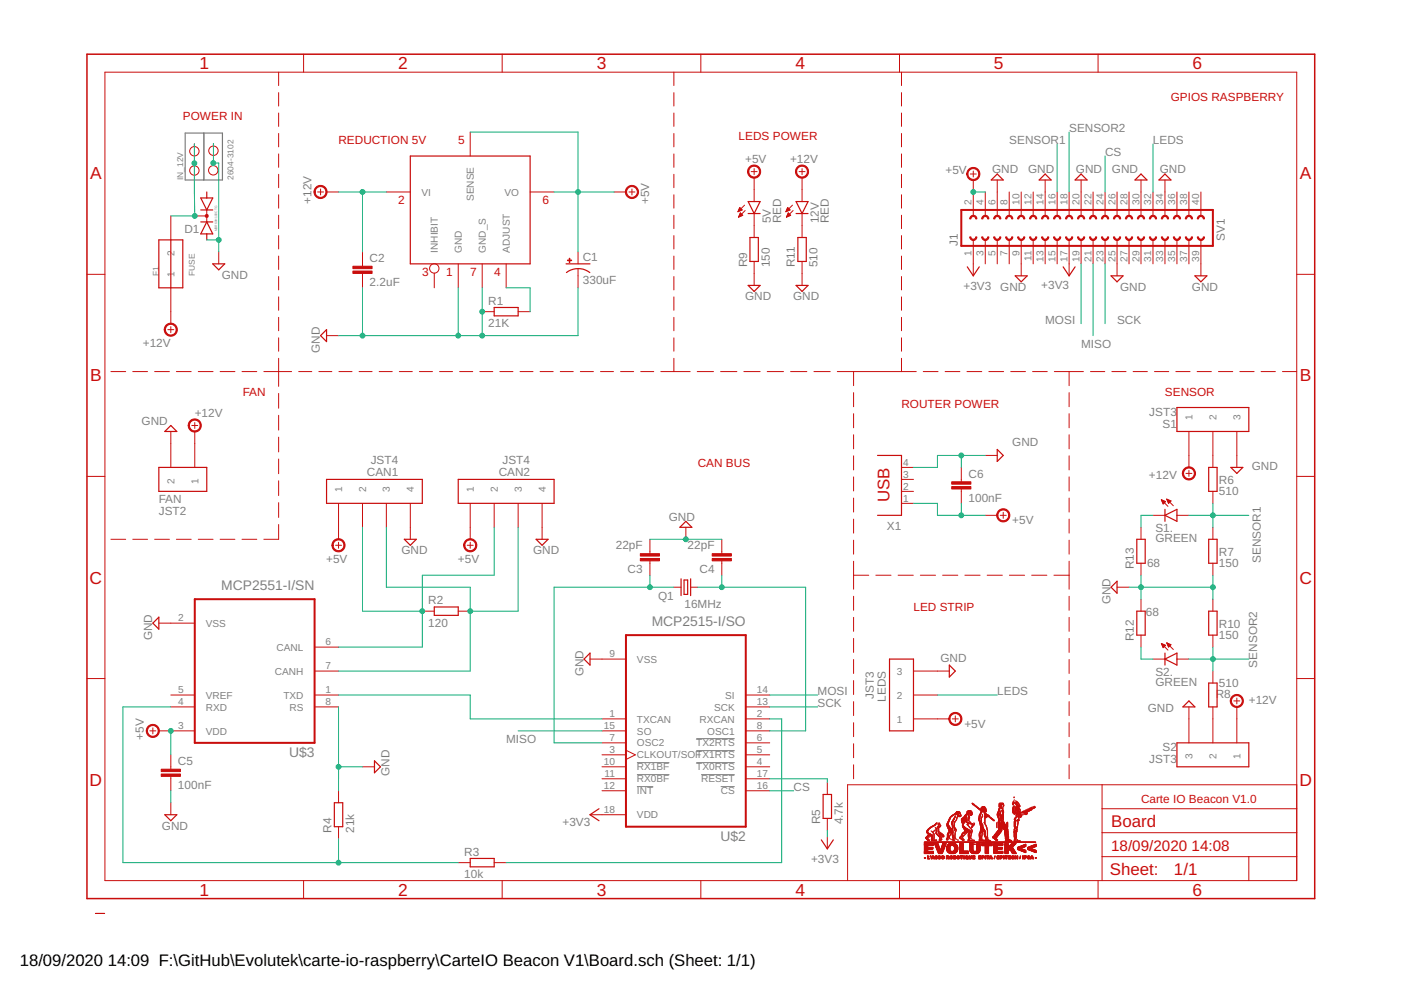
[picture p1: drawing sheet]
<svg xmlns="http://www.w3.org/2000/svg" width="297mm" height="210mm" viewBox="0 0 297 210" stroke-linecap="round" stroke-linejoin="round" font-family="sans-serif">
<defs><g id="words">
<g font-size="3.7" fill="#c90d0c">
<text x="42.3" y="14.7">1</text>
<text x="84.4" y="14.7">2</text>
<text x="126.5" y="14.7">3</text>
<text x="168.6" y="14.7">4</text>
<text x="210.7" y="14.7">5</text>
<text x="252.9" y="14.7">6</text>
<text x="19.1" y="38">A</text>
<text x="275.6" y="38">A</text>
<text x="19.1" y="80.9">B</text>
<text x="275.6" y="80.9">B</text>
<text x="19" y="123.7">C</text>
<text x="275.5" y="123.7">C</text>
<text x="19" y="166.6">D</text>
<text x="275.5" y="166.6">D</text>
<text x="42.3" y="189.9">1</text>
<text x="84.4" y="189.9">2</text>
<text x="126.5" y="189.9">3</text>
<text x="168.6" y="189.9">4</text>
<text x="210.7" y="189.9">5</text>
<text x="252.9" y="189.9">6</text>
</g>
<g font-size="3.6" fill="#c90d0c">
<text x="188.6" y="106.5" transform="rotate(-90 188.6 106.5)">USB</text>
<text x="235.6" y="175.3">Board</text>
<text x="235.3" y="185.6">Sheet:</text>
<text x="248.9" y="185.4">1/1</text>
</g>
<g font-size="3.5">
<text x="4.2" y="204.7">18/09/2020</text>
<text x="22.9" y="204.7">14:09 F:\GitHub\Evolutek\carte-io-raspberry\CarteIO Beacon V1\Board.sch (Sheet: 1/1)</text>
</g>
<g font-size="3.2" fill="#c90d0c">
<text x="235.6" y="180.4">18/09/2020</text>
<text x="252.6" y="180.4">14:08</text>
</g>
<g font-size="2.9" fill="#808080">
<text x="46.9" y="125.1">MCP2551-I/SN</text>
<text x="138.2" y="132.7">MCP2515-I/SO</text>
<text x="61.3" y="160.6">U$3</text>
<text x="152.7" y="178.4">U$2</text>
</g>
<g font-size="2.5" fill="#c90d0c">
<text x="248.2" y="21.4">GPIOS RASPBERRY</text>
<text x="38.8" y="25.5">POWER IN</text>
<text x="156.6" y="29.8">LEDS POWER</text>
<text x="71.8" y="30.5">REDUCTION 5V</text>
<text x="97.2" y="30.5">5</text>
<text x="84.4" y="43.2">2</text>
<text x="115" y="43.2">6</text>
<text x="89.5" y="58.5">3</text>
<text x="94.6" y="58.5">1</text>
<text x="99.7" y="58.5">7</text>
<text x="104.8" y="58.5">4</text>
<text x="51.5" y="83.9">FAN</text>
<text x="247" y="83.9">SENSOR</text>
<text x="191.1" y="86.4">ROUTER POWER</text>
<text x="148" y="99.1">CAN BUS</text>
<text x="193.7" y="129.6">LED STRIP</text>
<text x="241.9" y="170.2">Carte IO Beacon V1.0</text>
</g>
<g font-size="2.5" fill="#808080">
<text x="226.7" y="28">SENSOR2</text>
<text x="158" y="34.5">+5V</text>
<text x="167.5" y="34.5">+12V</text>
<text x="214" y="30.5">SENSOR1</text>
<text x="234.3" y="33.1">CS</text>
<text x="244.5" y="30.5">LEDS</text>
<text x="200.5" y="37">+5V</text>
<text x="210.3" y="36.8">GND</text>
<text x="218" y="36.8">GND</text>
<text x="228.1" y="36.8">GND</text>
<text x="235.7" y="36.8">GND</text>
<text x="245.9" y="36.8">GND</text>
<text x="66.1" y="43.2" transform="rotate(-90 66.1 43.2)">+12V</text>
<text x="137.7" y="43.3" transform="rotate(-90 137.7 43.3)">+5V</text>
<text x="163.4" y="47.3" transform="rotate(-90 163.4 47.3)">5V</text>
<text x="165.6" y="47.3" transform="rotate(-90 165.6 47.3)">RED</text>
<text x="173.6" y="47.3" transform="rotate(-90 173.6 47.3)">12V</text>
<text x="175.8" y="47.3" transform="rotate(-90 175.8 47.3)">RED</text>
<text x="39.1" y="49.3">D1</text>
<text x="203.1" y="52.1" transform="rotate(-90 203.1 52.1)">J1</text>
<text x="259.7" y="51.1" transform="rotate(-90 259.7 51.1)">SV1</text>
<text x="47" y="59.1">GND</text>
<text x="78.4" y="55.6">C2</text>
<text x="123.6" y="55.3">C1</text>
<text x="158.4" y="56.7" transform="rotate(-90 158.4 56.7)">R9</text>
<text x="163.2" y="56.7" transform="rotate(-90 163.2 56.7)">150</text>
<text x="168.5" y="56.7" transform="rotate(-90 168.5 56.7)">R11</text>
<text x="173.3" y="56.7" transform="rotate(-90 173.3 56.7)">510</text>
<text x="78.4" y="60.6">2.2uF</text>
<text x="103.5" y="64.6">R1</text>
<text x="123.6" y="60.1">330uF</text>
<text x="158" y="63.7">GND</text>
<text x="168.1" y="63.7">GND</text>
<text x="204.3" y="61.5">+3V3</text>
<text x="212.1" y="61.6">GND</text>
<text x="220.8" y="61.3">+3V3</text>
<text x="237.5" y="61.6">GND</text>
<text x="252.7" y="61.6">GND</text>
<text x="103.5" y="69.4">21K</text>
<text x="221.6" y="68.6">MOSI</text>
<text x="236.8" y="68.6">SCK</text>
<text x="30.3" y="73.6">+12V</text>
<text x="67.8" y="74.8" transform="rotate(-90 67.8 74.8)">GND</text>
<text x="229.2" y="73.7">MISO</text>
<text x="41.3" y="88.3">+12V</text>
<text x="243.7" y="88.2">JST3</text>
<text x="30" y="90.1">GND</text>
<text x="214.6" y="94.7">GND</text>
<text x="246.5" y="90.7">S1</text>
<text x="77.8" y="100.9">CAN1</text>
<text x="78.6" y="98.3">JST4</text>
<text x="105.7" y="100.9">CAN2</text>
<text x="106.5" y="98.3">JST4</text>
<text x="205.3" y="101.3">C6</text>
<text x="243.6" y="101.5">+12V</text>
<text x="265.4" y="99.7">GND</text>
<text x="33.7" y="106.7">FAN</text>
<text x="205.3" y="106.3">100nF</text>
<text x="258.4" y="104.9">510</text>
<text x="258.4" y="102.7">R6</text>
<text x="33.7" y="109.3">JST2</text>
<text x="141.8" y="110.4">GND</text>
<text x="188.1" y="112.3">X1</text>
<text x="214.6" y="111.2">+5V</text>
<text x="245" y="112.8">S1.</text>
<text x="69.1" y="119.3">+5V</text>
<text x="85.1" y="117.5">GND</text>
<text x="97.1" y="119.3">+5V</text>
<text x="113" y="117.5">GND</text>
<text x="130.6" y="116.5">22pF</text>
<text x="145.8" y="116.5">22pF</text>
<text x="245" y="115">GREEN</text>
<text x="258.4" y="117.9">R7</text>
<text x="267.3" y="119.4" transform="rotate(-90 267.3 119.4)">SENSOR1</text>
<text x="133.1" y="121.6">C3</text>
<text x="148.3" y="121.6">C4</text>
<text x="240.4" y="120.7" transform="rotate(-90 240.4 120.7)">R13</text>
<text x="243.2" y="120.2">68</text>
<text x="258.4" y="120.2">150</text>
<text x="90.8" y="128.1">R2</text>
<text x="139.5" y="127.3">Q1</text>
<text x="145.1" y="128.8">16MHz</text>
<text x="235.4" y="128.1" transform="rotate(-90 235.4 128.1)">GND</text>
<text x="242.9" y="130.6">68</text>
<text x="32.3" y="135.8" transform="rotate(-90 32.3 135.8)">GND</text>
<text x="90.8" y="132.9">120</text>
<text x="240.4" y="135.9" transform="rotate(-90 240.4 135.9)">R12</text>
<text x="258.4" y="135.4">150</text>
<text x="258.4" y="133.2">R10</text>
<text x="123.7" y="143.4" transform="rotate(-90 123.7 143.4)">GND</text>
<text x="199.4" y="140.4">GND</text>
<text x="245" y="143.3">S2.</text>
<text x="266.6" y="141.5" transform="rotate(-90 266.6 141.5)">SENSOR2</text>
<text x="173.3" y="147.4">MOSI</text>
<text x="173.3" y="149.9">SCK</text>
<text x="185.3" y="148.1" transform="rotate(-90 185.3 148.1)">JST3</text>
<text x="187.8" y="148.8" transform="rotate(-90 187.8 148.8)">LEDS</text>
<text x="211.4" y="147.4">LEDS</text>
<text x="245" y="145.4">GREEN</text>
<text x="257.8" y="148.1">R8</text>
<text x="258.4" y="145.6">510</text>
<text x="264.8" y="149.3">+12V</text>
<text x="204.5" y="154.3">+5V</text>
<text x="243.4" y="151">GND</text>
<text x="30.5" y="156.9" transform="rotate(-90 30.5 156.9)">+5V</text>
<text x="107.3" y="157.5">MISO</text>
<text x="243.7" y="161.8">JST3</text>
<text x="246.5" y="159.3">S2</text>
<text x="37.7" y="167.3">100nF</text>
<text x="37.7" y="162.2">C5</text>
<text x="82.6" y="164.5" transform="rotate(-90 82.6 164.5)">GND</text>
<text x="168.3" y="167.7">CS</text>
<text x="34.3" y="175.9">GND</text>
<text x="70.3" y="176.6" transform="rotate(-90 70.3 176.6)">R4</text>
<text x="75.1" y="176.6" transform="rotate(-90 75.1 176.6)">21k</text>
<text x="119.3" y="175.1">+3V3</text>
<text x="173.9" y="174.8" transform="rotate(-90 173.9 174.8)">R5</text>
<text x="178.7" y="174.8" transform="rotate(-90 178.7 174.8)">4.7k</text>
<text x="98.4" y="181.4">R3</text>
<text x="171.9" y="182.9">+3V3</text>
<text x="98.4" y="186.2">10k</text>
</g>
<g font-size="2.1" fill="#808080">
<text x="89.3" y="41.5">VI</text>
<text x="107" y="41.5">VO</text>
<text x="100.5" y="42.6" transform="rotate(-90 100.5 42.6)">SENSE</text>
<text x="206" y="43.4" transform="rotate(-90 206 43.4)">2</text>
<text x="208.5" y="43.4" transform="rotate(-90 208.5 43.4)">4</text>
<text x="211.1" y="43.4" transform="rotate(-90 211.1 43.4)">6</text>
<text x="213.6" y="43.4" transform="rotate(-90 213.6 43.4)">8</text>
<text x="216.2" y="43.4" transform="rotate(-90 216.2 43.4)">10</text>
<text x="218.7" y="43.4" transform="rotate(-90 218.7 43.4)">12</text>
<text x="221.2" y="43.4" transform="rotate(-90 221.2 43.4)">14</text>
<text x="223.8" y="43.4" transform="rotate(-90 223.8 43.4)">16</text>
<text x="226.3" y="43.4" transform="rotate(-90 226.3 43.4)">18</text>
<text x="228.9" y="43.4" transform="rotate(-90 228.9 43.4)">20</text>
<text x="231.4" y="43.4" transform="rotate(-90 231.4 43.4)">22</text>
<text x="233.9" y="43.4" transform="rotate(-90 233.9 43.4)">24</text>
<text x="236.5" y="43.4" transform="rotate(-90 236.5 43.4)">26</text>
<text x="239" y="43.4" transform="rotate(-90 239 43.4)">28</text>
<text x="241.6" y="43.4" transform="rotate(-90 241.6 43.4)">30</text>
<text x="244.1" y="43.4" transform="rotate(-90 244.1 43.4)">32</text>
<text x="246.6" y="43.4" transform="rotate(-90 246.6 43.4)">34</text>
<text x="249.2" y="43.4" transform="rotate(-90 249.2 43.4)">36</text>
<text x="251.7" y="43.4" transform="rotate(-90 251.7 43.4)">38</text>
<text x="254.3" y="43.4" transform="rotate(-90 254.3 43.4)">40</text>
<text x="92.8" y="53.6" transform="rotate(-90 92.8 53.6)">INHIBIT</text>
<text x="97.9" y="53.6" transform="rotate(-90 97.9 53.6)">GND</text>
<text x="103" y="53.6" transform="rotate(-90 103 53.6)">GND_S</text>
<text x="108.1" y="53.6" transform="rotate(-90 108.1 53.6)">ADJUST</text>
<text x="37" y="58.7" transform="rotate(-90 37 58.7)">1</text>
<text x="37" y="54.4" transform="rotate(-90 37 54.4)">2</text>
<text x="206" y="54.4" transform="rotate(-90 206 54.4)">1</text>
<text x="208.5" y="54.4" transform="rotate(-90 208.5 54.4)">3</text>
<text x="211.1" y="54.4" transform="rotate(-90 211.1 54.4)">5</text>
<text x="213.6" y="54.4" transform="rotate(-90 213.6 54.4)">7</text>
<text x="216.2" y="54.4" transform="rotate(-90 216.2 54.4)">9</text>
<text x="218.7" y="55.4" transform="rotate(-90 218.7 55.4)">11</text>
<text x="221.2" y="55.6" transform="rotate(-90 221.2 55.6)">13</text>
<text x="223.8" y="55.6" transform="rotate(-90 223.8 55.6)">15</text>
<text x="226.3" y="55.6" transform="rotate(-90 226.3 55.6)">17</text>
<text x="228.9" y="55.6" transform="rotate(-90 228.9 55.6)">19</text>
<text x="231.4" y="55.6" transform="rotate(-90 231.4 55.6)">21</text>
<text x="233.9" y="55.6" transform="rotate(-90 233.9 55.6)">23</text>
<text x="236.5" y="55.6" transform="rotate(-90 236.5 55.6)">25</text>
<text x="239" y="55.6" transform="rotate(-90 239 55.6)">27</text>
<text x="241.6" y="55.6" transform="rotate(-90 241.6 55.6)">29</text>
<text x="244.1" y="55.6" transform="rotate(-90 244.1 55.6)">31</text>
<text x="246.6" y="55.6" transform="rotate(-90 246.6 55.6)">33</text>
<text x="249.2" y="55.6" transform="rotate(-90 249.2 55.6)">35</text>
<text x="251.7" y="55.6" transform="rotate(-90 251.7 55.6)">37</text>
<text x="254.3" y="55.6" transform="rotate(-90 254.3 55.6)">39</text>
<text x="252.8" y="89.1" transform="rotate(-90 252.8 89.1)">1</text>
<text x="257.9" y="89.1" transform="rotate(-90 257.9 89.1)">2</text>
<text x="263" y="89.1" transform="rotate(-90 263 89.1)">3</text>
<text x="191.5" y="101.3">3</text>
<text x="191.5" y="98.7">4</text>
<text x="37" y="102.6" transform="rotate(-90 37 102.6)">2</text>
<text x="42.1" y="102.6" transform="rotate(-90 42.1 102.6)">1</text>
<text x="72.5" y="104.4" transform="rotate(-90 72.5 104.4)">1</text>
<text x="77.6" y="104.4" transform="rotate(-90 77.6 104.4)">2</text>
<text x="82.7" y="104.4" transform="rotate(-90 82.7 104.4)">3</text>
<text x="87.8" y="104.4" transform="rotate(-90 87.8 104.4)">4</text>
<text x="100.5" y="104.4" transform="rotate(-90 100.5 104.4)">1</text>
<text x="105.5" y="104.4" transform="rotate(-90 105.5 104.4)">2</text>
<text x="110.6" y="104.4" transform="rotate(-90 110.6 104.4)">3</text>
<text x="115.7" y="104.4" transform="rotate(-90 115.7 104.4)">4</text>
<text x="191.5" y="106.4">1</text>
<text x="191.5" y="103.8">2</text>
<text x="37.8" y="131.8">2</text>
<text x="43.6" y="132.9">VSS</text>
<text x="58.7" y="138">CANL</text>
<text x="69" y="136.8">6</text>
<text x="58.3" y="143">CANH</text>
<text x="69" y="141.9">7</text>
<text x="129.2" y="139.4">9</text>
<text x="135.1" y="140.5">VSS</text>
<text x="190.1" y="143">3</text>
<text x="37.8" y="149.5">4</text>
<text x="37.8" y="147">5</text>
<text x="43.6" y="148.1">VREF</text>
<text x="60.1" y="148.1">TXD</text>
<text x="69" y="149.5">8</text>
<text x="69" y="147">1</text>
<text x="153.8" y="148.1">SI</text>
<text x="160.4" y="149.5">13</text>
<text x="160.4" y="147">14</text>
<text x="190.1" y="148.1">2</text>
<text x="37.8" y="154.6">3</text>
<text x="43.6" y="155.7">VDD</text>
<text x="43.6" y="150.7">RXD</text>
<text x="61.4" y="150.7">RS</text>
<text x="128" y="154.6">15</text>
<text x="129.2" y="152.1">1</text>
<text x="135.1" y="155.7">SO</text>
<text x="135.1" y="153.2">TXCAN</text>
<text x="148.3" y="153.2">RXCAN</text>
<text x="150" y="155.7">OSC1</text>
<text x="151.4" y="150.7">SCK</text>
<text x="160.4" y="154.6">8</text>
<text x="160.4" y="152.1">2</text>
<text x="190.1" y="153.2">1</text>
<text x="129.2" y="159.7">3</text>
<text x="129.2" y="157.2">7</text>
<text x="135.1" y="160.8">CLKOUT/SOF</text>
<text x="135.1" y="158.3">OSC2</text>
<text x="147.6" y="160.8">TX1RTS</text>
<text x="147.6" y="158.3">TX2RTS</text>
<text x="160.4" y="159.7">5</text>
<text x="160.4" y="157.2">6</text>
<text x="252.8" y="161" transform="rotate(-90 252.8 161)">3</text>
<text x="257.9" y="161" transform="rotate(-90 257.9 161)">2</text>
<text x="263" y="161" transform="rotate(-90 263 161)">1</text>
<text x="128" y="167.3">12</text>
<text x="128" y="162.2">10</text>
<text x="128.2" y="164.8">11</text>
<text x="135.1" y="165.9">RX0BF</text>
<text x="135.1" y="163.4">RX1BF</text>
<text x="147.6" y="163.4">TX0RTS</text>
<text x="148.7" y="165.9">RESET</text>
<text x="160.4" y="167.3">16</text>
<text x="160.4" y="164.8">17</text>
<text x="160.4" y="162.2">4</text>
<text x="128" y="172.4">18</text>
<text x="135.1" y="173.5">VDD</text>
<text x="135.1" y="168.4">INT</text>
<text x="152.8" y="168.4">CS</text>
</g>
<g font-size="1.8" fill="#808080">
<text x="38.8" y="38.2" transform="rotate(-90 38.8 38.2)">IN_12V</text>
<text x="49.5" y="38.2" transform="rotate(-90 49.5 38.2)">2604-3102</text>
<text x="33.7" y="58.5" transform="rotate(-90 33.7 58.5)">F1</text>
<text x="41.3" y="58.5" transform="rotate(-90 41.3 58.5)">FUSE</text>
</g>
<text font-size=".7" fill="#808080" x="46" y="49.1" transform="rotate(-90 46 49.1)">MBR60H100CTG</text>
</g></defs>
<path d="M39.3 28.2h7.9v10h-7.9zM43.2 28.2v10" fill="none" stroke="#808080" stroke-width=".25"/>
<path d="M147.6 159.2h8.2M147.6 156.6h8.2M135 166.8h3.5M135 164.2h6.9M135 161.7h6.9M147.6 161.7h8.2M148.7 164.2h7.1M152.8 166.8h3" fill="none" stroke="#808080" stroke-width=".21"/>
<g fill="#c90d0c" stroke="#c90d0c" stroke-width=".21">
<path d="M196.6 182.1h.5z"/>
<path d="M197.4 182.1h.3z"/>
<path d="M198 182.1h.2z"/>
<path d="M198.3 182.1h.4z"/>
<path d="M199 182.1h.3z"/>
<path d="M199.7 182.1h.3z"/>
<path d="M200.6 182.1h.3z"/>
<path d="M201.1 182.1h.2z"/>
<path d="M201.5 182.1h.4z"/>
<path d="M202.1 182.1h.5z"/>
<path d="M203 182.1h.3z"/>
<path d="M203.8 182.1h.2z"/>
<path d="M204.3 182.1h.2z"/>
<path d="M204.8 182.1h.5z"/>
<path d="M205.5 182.1h.4z"/>
<path d="M206.2 182.1h.5z"/>
<path d="M207.5 182.1h.5z"/>
<path d="M208.2 182.1h.1z"/>
<path d="M208.8 182.1h.2z"/>
<path d="M209.3 182.1h.2z"/>
<path d="M209.7 182.1h.3z"/>
<path d="M210.2 182.1h.3z"/>
<path d="M211.4 182.1h.5z"/>
<path d="M212.1 182.1h.1z"/>
<path d="M212.7 182.1h.2z"/>
<path d="M213.2 182.1h.2z"/>
<path d="M213.8 182.1h.5z"/>
<path d="M214.6 182.1h.3z"/>
<path d="M215.1 182.1h.2z"/>
<path d="M215.6 182.1h.2z"/>
<path d="M216.8 182.1h.2z"/>
<path d="M217.1 182.1h.3z"/>
<path d="M217.9 182.1h.4z"/>
<path d="M218.4 182.1h.2z"/>
<path d="M218.9 182.1h.2z"/>
<path d="M196.6 182l.5 .1z"/>
<path d="M197.4 182l.3 .1z"/>
<path d="M197.9 182l.3 .1z"/>
<path d="M198.3 182l.4 .1z"/>
<path d="M198.9 182l.5 .1z"/>
<path d="M199.6 182l.6 .1z"/>
<path d="M200.6 182l.3 .1z"/>
<path d="M201 182l.3 .1z"/>
<path d="M201.4 182l.5 .1z"/>
<path d="M202.1 182l.6 .1z"/>
<path d="M202.9 182l.5 .1z"/>
<path d="M203.8 182l.2 .1z"/>
<path d="M204.3 182l.2 .1z"/>
<path d="M204.7 182l.6 .1z"/>
<path d="M205.5 182l.5 .1z"/>
<path d="M206.2 182l.5 .1z"/>
<path d="M207.5 182l.5 .1z"/>
<path d="M208.1 182l.3 .1z"/>
<path d="M208.8 182l.2 .1z"/>
<path d="M209.3 182l.2 .1z"/>
<path d="M209.7 182l.3 .1z"/>
<path d="M210.2 182l.2 .1z"/>
<path d="M211.4 182l.5 .1z"/>
<path d="M212 182l.3 .1z"/>
<path d="M212.7 182l.2 .1z"/>
<path d="M213.2 182l.2 .1z"/>
<path d="M213.8 182l.5 .1z"/>
<path d="M214.5 182l.5 .1z"/>
<path d="M215.1 182l.3 .1z"/>
<path d="M215.6 182l.2 .1z"/>
<path d="M216.8 182l.2 .1z"/>
<path d="M217.1 182l.3 .1z"/>
<path d="M217.9 182l.4 .1z"/>
<path d="M218.5 182l.2 .1z"/>
<path d="M218.9 182l.2 .1z"/>
<path d="M196.6 182h.5z"/>
<path d="M197.5 182h.6z"/>
<path d="M198.2 182h.3z"/>
<path d="M198.5 182h.3z"/>
<path d="M198.9 182h.2z"/>
<path d="M199.2 182h.2z"/>
<path d="M199.6 182h.6z"/>
<path d="M200.6 182h.3z"/>
<path d="M201 182h.3z"/>
<path d="M201.4 182h.6z"/>
<path d="M202.1 182h.6z"/>
<path d="M202.9 182h.6z"/>
<path d="M203.8 182h.2z"/>
<path d="M204.3 182h.2z"/>
<path d="M204.7 182h.6z"/>
<path d="M205.4 182h.6z"/>
<path d="M206.2 182h.5z"/>
<path d="M207.5 182h.5z"/>
<path d="M208.1 182h.3z"/>
<path d="M208.8 182h.2z"/>
<path d="M209.3 182h.2z"/>
<path d="M209.7 182h.7z"/>
<path d="M211.4 182h.5z"/>
<path d="M212 182h.3z"/>
<path d="M212.7 182h.2z"/>
<path d="M213.2 182h.2z"/>
<path d="M213.8 182h.5z"/>
<path d="M214.5 182h.5z"/>
<path d="M215.1 182h.3z"/>
<path d="M215.6 182h.2z"/>
<path d="M216.8 182h.2z"/>
<path d="M217.1 182h.3z"/>
<path d="M217.8 182h.3z"/>
<path d="M218.1 182h.3z"/>
<path d="M218.5 182h.6z"/>
<path d="M196 181.9l.2 .1z"/>
<path d="M196.6 181.9l.2 .1z"/>
<path d="M197.5 181.9l.6 .1z"/>
<path d="M198.2 181.9l.2 .1z"/>
<path d="M198.6 181.9l.2 .1z"/>
<path d="M198.9 181.9l.2 .1z"/>
<path d="M199.2 181.9l.3 .1z"/>
<path d="M199.6 181.9l.2 .1z"/>
<path d="M200 181.9l.2 .1z"/>
<path d="M200.6 181.9l.3 .1z"/>
<path d="M201 181.9l.2 .1z"/>
<path d="M201.4 181.9l.2 .1z"/>
<path d="M201.8 181.9l.2 .1z"/>
<path d="M202.1 181.9l.2 .1z"/>
<path d="M202.5 181.9l.2 .1z"/>
<path d="M202.8 181.9l.3 .1z"/>
<path d="M203.2 181.9l.3 .1z"/>
<path d="M203.8 181.9l.2 .1z"/>
<path d="M204.3 181.9l.2 .1z"/>
<path d="M204.6 181.9l.3 .1z"/>
<path d="M204.9 181.9l.4 .1z"/>
<path d="M205.4 181.9l.2 .1z"/>
<path d="M205.8 181.9l.2 .1z"/>
<path d="M206.2 181.9l.2 .1z"/>
<path d="M207.5 181.9l.2 .1z"/>
<path d="M208.1 181.9l.3 .1z"/>
<path d="M208.8 181.9l.2 .1z"/>
<path d="M209.3 181.9l.2 .1z"/>
<path d="M209.8 181.9l.6 .1z"/>
<path d="M211.4 181.9l.2 .1z"/>
<path d="M212 181.9l.3 .1z"/>
<path d="M212.7 181.9l.2 .1z"/>
<path d="M213.2 181.9l.2 .1z"/>
<path d="M213.7 181.9l.3 .1z"/>
<path d="M214.4 181.9l.3 .1z"/>
<path d="M214.8 181.9l.2 .1z"/>
<path d="M215.1 181.9l.3 .1z"/>
<path d="M215.6 181.9l.2 .1z"/>
<path d="M216.8 181.9l.2 .1z"/>
<path d="M217.1 181.9l.3 .1z"/>
<path d="M217.8 181.9l.2 .1z"/>
<path d="M218.2 181.9l.2 .1z"/>
<path d="M218.5 181.9l.6 .1z"/>
<path d="M219.5 181.9l.3 .1z"/>
<path d="M196 181.9h.2z"/>
<path d="M196.6 181.9h.2z"/>
<path d="M197.5 181.9h.6z"/>
<path d="M198.6 181.9h.2z"/>
<path d="M199.2 181.9h.3z"/>
<path d="M199.5 181.9h.3z"/>
<path d="M200 181.9h.2z"/>
<path d="M200.6 181.9h.3z"/>
<path d="M201 181.9h.2z"/>
<path d="M201.3 181.9h.3z"/>
<path d="M201.8 181.9h.2z"/>
<path d="M202.1 181.9h.2z"/>
<path d="M202.5 181.9h.2z"/>
<path d="M202.8 181.9h.2z"/>
<path d="M203.3 181.9h.2z"/>
<path d="M203.8 181.9h.2z"/>
<path d="M204.3 181.9h.2z"/>
<path d="M204.6 181.9h.2z"/>
<path d="M205.1 181.9h.2z"/>
<path d="M205.4 181.9h.2z"/>
<path d="M205.8 181.9h.2z"/>
<path d="M206.2 181.9h.2z"/>
<path d="M207.5 181.9h.2z"/>
<path d="M208.1 181.9h.3z"/>
<path d="M208.8 181.9h.2z"/>
<path d="M209.3 181.9h.2z"/>
<path d="M209.8 181.9h.6z"/>
<path d="M211.4 181.9h.2z"/>
<path d="M212 181.9h.3z"/>
<path d="M212.7 181.9h.2z"/>
<path d="M213.2 181.9h.2z"/>
<path d="M213.7 181.9h.3z"/>
<path d="M214.4 181.9h.2z"/>
<path d="M214.9 181.9h.1z"/>
<path d="M215.1 181.9h.3z"/>
<path d="M215.6 181.9h.2z"/>
<path d="M216.8 181.9h.2z"/>
<path d="M217.1 181.9h.3z"/>
<path d="M218.2 181.9h.2z"/>
<path d="M218.5 181.9h.6z"/>
<path d="M219.5 181.9h.3z"/>
<path d="M196 181.8l.2 .1z"/>
<path d="M196.6 181.8l.2 .1z"/>
<path d="M197.5 181.8l.3 .1z"/>
<path d="M197.8 181.8l.3 .1z"/>
<path d="M198.4 181.8l.4 .1z"/>
<path d="M199.1 181.8l.3 .1z"/>
<path d="M199.5 181.8l.2 .1z"/>
<path d="M200 181.8l.3 .1z"/>
<path d="M200.7 181.8l.5 .1z"/>
<path d="M201.3 181.8l.3 .1z"/>
<path d="M201.8 181.8l.2 .1z"/>
<path d="M202.1 181.8l.6 .1z"/>
<path d="M202.8 181.8l.2 .1z"/>
<path d="M203.3 181.8l.2 .1z"/>
<path d="M203.8 181.8l.2 .1z"/>
<path d="M204.3 181.8l.2 .1z"/>
<path d="M204.6 181.8l.2 .1z"/>
<path d="M205.1 181.8l.2 .1z"/>
<path d="M205.4 181.8l.2 .1z"/>
<path d="M205.8 181.8l.2 .1z"/>
<path d="M206.2 181.8l.5 .1z"/>
<path d="M207.5 181.8l.5 .1z"/>
<path d="M208.1 181.8l.5 .1z"/>
<path d="M208.8 181.8l.2 .1z"/>
<path d="M209.3 181.8l.2 .1z"/>
<path d="M209.8 181.8l.2 .1z"/>
<path d="M210.1 181.8l.3 .1z"/>
<path d="M211.4 181.8l.5 .1z"/>
<path d="M212 181.8l.5 .1z"/>
<path d="M212.7 181.8l.2 .1z"/>
<path d="M213.2 181.8l.2 .1z"/>
<path d="M213.8 181.8l.5 .1z"/>
<path d="M214.4 181.8l.2 .1z"/>
<path d="M215.1 181.8l.7 .1z"/>
<path d="M216.8 181.8l.2 .1z"/>
<path d="M217.1 181.8l.6 .1z"/>
<path d="M218 181.8l.4 .1z"/>
<path d="M218.5 181.8l.2 .1z"/>
<path d="M218.8 181.8l.2 .1z"/>
<path d="M219.5 181.8l.3 .1z"/>
<path d="M196.6 181.8h.2z"/>
<path d="M197.5 181.8h.3z"/>
<path d="M197.8 181.8h.3z"/>
<path d="M198.3 181.8h.5z"/>
<path d="M199 181.8h.4z"/>
<path d="M199.5 181.8h.2z"/>
<path d="M200 181.8h.3z"/>
<path d="M200.7 181.8h.5z"/>
<path d="M201.3 181.8h.3z"/>
<path d="M201.8 181.8h.2z"/>
<path d="M202.1 181.8h.6z"/>
<path d="M202.8 181.8h.2z"/>
<path d="M203.3 181.8h.2z"/>
<path d="M203.8 181.8h.2z"/>
<path d="M204.3 181.8h.2z"/>
<path d="M204.6 181.8h.2z"/>
<path d="M205.1 181.8h.2z"/>
<path d="M205.4 181.8h.2z"/>
<path d="M205.8 181.8h.2z"/>
<path d="M206.2 181.8h.5z"/>
<path d="M207.5 181.8h.5z"/>
<path d="M208.1 181.8h.6z"/>
<path d="M208.8 181.8h.2z"/>
<path d="M209.3 181.8h.2z"/>
<path d="M209.8 181.8h.3z"/>
<path d="M210.1 181.8h.2z"/>
<path d="M211.4 181.8h.5z"/>
<path d="M212 181.8h.6z"/>
<path d="M212.7 181.8h.2z"/>
<path d="M213.2 181.8h.2z"/>
<path d="M213.8 181.8h.5z"/>
<path d="M214.4 181.8h.2z"/>
<path d="M215.1 181.8h.7z"/>
<path d="M216.8 181.8h.2z"/>
<path d="M217.2 181.8h.5z"/>
<path d="M217.9 181.8h.5z"/>
<path d="M218.6 181.8h.1z"/>
<path d="M218.8 181.8h.2z"/>
<path d="M196.6 181.7l.2 .1z"/>
<path d="M197.6 181.7l.2 .1z"/>
<path d="M197.8 181.7l.2 .1z"/>
<path d="M198.2 181.7l.5 .1z"/>
<path d="M198.9 181.7l.4 .1z"/>
<path d="M199.5 181.7l.2 .1z"/>
<path d="M200 181.7l.3 .1z"/>
<path d="M200.7 181.7l.6 .1z"/>
<path d="M201.3 181.7l.3 .1z"/>
<path d="M201.8 181.7l.2 .1z"/>
<path d="M202.1 181.7l.6 .1z"/>
<path d="M202.8 181.7l.2 .1z"/>
<path d="M203.3 181.7l.2 .1z"/>
<path d="M203.8 181.7l.2 .1z"/>
<path d="M204.3 181.7l.2 .1z"/>
<path d="M204.6 181.7l.2 .1z"/>
<path d="M205.1 181.7l.2 .1z"/>
<path d="M205.4 181.7l.2 .1z"/>
<path d="M205.8 181.7l.2 .1z"/>
<path d="M206.2 181.7l.5 .1z"/>
<path d="M207.5 181.7l.5 .1z"/>
<path d="M208.1 181.7l.3 .1z"/>
<path d="M208.5 181.7l.2 .1z"/>
<path d="M208.8 181.7l.2 .1z"/>
<path d="M209.3 181.7l.2 .1z"/>
<path d="M209.8 181.7l.3 .1z"/>
<path d="M210.1 181.7l.2 .1z"/>
<path d="M211.4 181.7l.5 .1z"/>
<path d="M212 181.7l.3 .1z"/>
<path d="M212.4 181.7l.2 .1z"/>
<path d="M212.7 181.7l.2 .1z"/>
<path d="M213.2 181.7l.2 .1z"/>
<path d="M213.8 181.7l.5 .1z"/>
<path d="M214.4 181.7l.2 .1z"/>
<path d="M215.1 181.7l.7 .1z"/>
<path d="M216.8 181.7l.2 .1z"/>
<path d="M217.1 181.7l.3 .1z"/>
<path d="M217.5 181.7l.2 .1z"/>
<path d="M217.8 181.7l.5 .1z"/>
<path d="M218.6 181.7l.2 .1z"/>
<path d="M218.8 181.7l.2 .1z"/>
<path d="M196.6 181.7h.2z"/>
<path d="M197.2 181.7h.2z"/>
<path d="M197.6 181.7h.4z"/>
<path d="M198.2 181.7h.3z"/>
<path d="M198.9 181.7h.3z"/>
<path d="M199.5 181.7h.3z"/>
<path d="M200 181.7h.2z"/>
<path d="M200.6 181.7h.3z"/>
<path d="M201.1 181.7h.2z"/>
<path d="M201.4 181.7h.2z"/>
<path d="M201.8 181.7h.2z"/>
<path d="M202.1 181.7h.2z"/>
<path d="M202.5 181.7h.2z"/>
<path d="M202.8 181.7h.2z"/>
<path d="M203.3 181.7h.2z"/>
<path d="M203.8 181.7h.2z"/>
<path d="M204.3 181.7h.2z"/>
<path d="M204.6 181.7h.2z"/>
<path d="M205.1 181.7h.2z"/>
<path d="M205.4 181.7h.2z"/>
<path d="M205.8 181.7h.2z"/>
<path d="M206.2 181.7h.2z"/>
<path d="M207.5 181.7h.2z"/>
<path d="M208.1 181.7h.3z"/>
<path d="M208.5 181.7h.2z"/>
<path d="M208.8 181.7h.2z"/>
<path d="M209.3 181.7h.2z"/>
<path d="M209.9 181.7h.3z"/>
<path d="M211.4 181.7h.2z"/>
<path d="M212 181.7h.3z"/>
<path d="M212.4 181.7h.2z"/>
<path d="M212.7 181.7h.2z"/>
<path d="M213.2 181.7h.2z"/>
<path d="M213.7 181.7h.3z"/>
<path d="M214.4 181.7h.2z"/>
<path d="M215.1 181.7h.3z"/>
<path d="M215.6 181.7h.2z"/>
<path d="M216.8 181.7h.2z"/>
<path d="M217.1 181.7h.3z"/>
<path d="M217.5 181.7h.2z"/>
<path d="M217.8 181.7h.3z"/>
<path d="M218.6 181.7h.4z"/>
<path d="M196.6 181.6l.2 .1z"/>
<path d="M197.2 181.6l.2 .1z"/>
<path d="M197.6 181.6l.4 .1z"/>
<path d="M198.2 181.6l.2 .1z"/>
<path d="M198.6 181.6l.2 .1z"/>
<path d="M198.9 181.6l.2 .1z"/>
<path d="M199.2 181.6l.2 .1z"/>
<path d="M199.6 181.6l.2 .1z"/>
<path d="M199.9 181.6l.3 .1z"/>
<path d="M200.6 181.6l.3 .1z"/>
<path d="M201 181.6l.3 .1z"/>
<path d="M201.4 181.6l.2 .1z"/>
<path d="M201.7 181.6l.3 .1z"/>
<path d="M202.1 181.6l.2 .1z"/>
<path d="M202.5 181.6l.2 .1z"/>
<path d="M202.8 181.6l.3 .1z"/>
<path d="M203.2 181.6l.3 .1z"/>
<path d="M203.6 181.6l.6 .1z"/>
<path d="M204.3 181.6l.2 .1z"/>
<path d="M204.7 181.6l.2 .1z"/>
<path d="M205 181.6l.3 .1z"/>
<path d="M205.4 181.6l.2 .1z"/>
<path d="M205.8 181.6l.2 .1z"/>
<path d="M206.2 181.6l.2 .1z"/>
<path d="M207.5 181.6l.2 .1z"/>
<path d="M208.1 181.6l.3 .1z"/>
<path d="M208.5 181.6l.2 .1z"/>
<path d="M208.8 181.6l.2 .1z"/>
<path d="M209.1 181.6l.6 .1z"/>
<path d="M209.9 181.6l.3 .1z"/>
<path d="M211.4 181.6l.2 .1z"/>
<path d="M212 181.6l.3 .1z"/>
<path d="M212.4 181.6l.2 .1z"/>
<path d="M212.7 181.6l.2 .1z"/>
<path d="M213 181.6l.6 .1z"/>
<path d="M213.7 181.6l.3 .1z"/>
<path d="M214.4 181.6l.3 .1z"/>
<path d="M214.8 181.6l.2 .1z"/>
<path d="M215.1 181.6l.3 .1z"/>
<path d="M215.6 181.6l.2 .1z"/>
<path d="M216.8 181.6l.2 .1z"/>
<path d="M217.1 181.6l.3 .1z"/>
<path d="M217.5 181.6l.2 .1z"/>
<path d="M217.8 181.6l.2 .1z"/>
<path d="M218.2 181.6l.2 .1z"/>
<path d="M218.6 181.6l.4 .1z"/>
<path d="M196.6 181.6h.2z"/>
<path d="M197.2 181.6h.2z"/>
<path d="M197.7 181.6h.3z"/>
<path d="M198.2 181.6h.6z"/>
<path d="M198.9 181.6h.5z"/>
<path d="M199.6 181.6h.6z"/>
<path d="M200.7 181.6h.6z"/>
<path d="M201.4 181.6h.6z"/>
<path d="M202.1 181.6h.6z"/>
<path d="M202.9 181.6h.5z"/>
<path d="M203.5 181.6h.7z"/>
<path d="M204.3 181.6h.2z"/>
<path d="M204.7 181.6h.5z"/>
<path d="M205.4 181.6h.2z"/>
<path d="M205.8 181.6h.2z"/>
<path d="M206.2 181.6h.5z"/>
<path d="M207.5 181.6h.5z"/>
<path d="M208.1 181.6h.6z"/>
<path d="M208.8 181.6h.2z"/>
<path d="M209.1 181.6h.6z"/>
<path d="M209.9 181.6h.3z"/>
<path d="M211.4 181.6h.5z"/>
<path d="M212 181.6h.6z"/>
<path d="M212.7 181.6h.2z"/>
<path d="M213 181.6h.6z"/>
<path d="M213.8 181.6h.5z"/>
<path d="M214.5 181.6h.5z"/>
<path d="M215.1 181.6h.3z"/>
<path d="M215.6 181.6h.2z"/>
<path d="M216.8 181.6h.2z"/>
<path d="M217.2 181.6h.5z"/>
<path d="M217.8 181.6h.6z"/>
<path d="M218.6 181.6h.3z"/>
<path d="M196.6 181.5h.2z"/>
<path d="M197.2 181.5h.2z"/>
<path d="M197.7 181.5h.3z"/>
<path d="M198.3 181.5h.4z"/>
<path d="M198.9 181.5h.5z"/>
<path d="M199.6 181.5h.6z"/>
<path d="M200.7 181.5h.5z"/>
<path d="M201.5 181.5h.4z"/>
<path d="M202.1 181.5h.6z"/>
<path d="M202.9 181.5h.5z"/>
<path d="M203.5 181.5h.7z"/>
<path d="M204.3 181.5h.2z"/>
<path d="M204.7 181.5h.5z"/>
<path d="M205.4 181.5h.2z"/>
<path d="M205.8 181.5h.2z"/>
<path d="M206.2 181.5h.5z"/>
<path d="M207.5 181.5h.5z"/>
<path d="M208.1 181.5h.6z"/>
<path d="M208.8 181.5h.2z"/>
<path d="M209.1 181.5h.6z"/>
<path d="M210 181.5h.2z"/>
<path d="M206.3 179h.5z"/>
<path d="M212 181.5h.6z"/>
<path d="M212.7 181.5h.2z"/>
<path d="M213 181.5h.6z"/>
<path d="M213.8 181.5h.5z"/>
<path d="M214.5 181.5h.5z"/>
<path d="M215.1 181.5h.3z"/>
<path d="M215.6 181.5h.2z"/>
<path d="M216.8 181.5h.2z"/>
<path d="M217.1 181.5h.6z"/>
<path d="M217.9 181.5h.4z"/>
<path d="M218.7 181.5h.2z"/>
<path d="M197.7 181.5h.2z"/>
<path d="M198.4 181.5h.2z"/>
<path d="M199 181.5h.3z"/>
<path d="M199.7 181.5h.3z"/>
<path d="M200.6 181.5h.5z"/>
<path d="M201.6 181.5h.2z"/>
<path d="M202.2 181.5h.4z"/>
<path d="M203 181.5h.3z"/>
<path d="M203.6 181.5h.6z"/>
<path d="M204.8 181.5h.3z"/>
<path d="M205.9 181.5h.1z"/>
<path d="M208.2 181.5h.3z"/>
<path d="M211.4 181.5h.5z"/>
<path d="M212.1 181.5h.3z"/>
<path d="M214.6 181.5h.3z"/>
<path d="M215.2 181.5h.1z"/>
<path d="M217.1 181.5h.5z"/>
<path d="M218 181.5h.2z"/>
<path d="M196 181h1.9z"/>
<path d="M199 181h.7z"/>
<path d="M201.5 181h.8z"/>
<path d="M203.5 181h1.8z"/>
<path d="M206.2 181h1z"/>
<path d="M208.9 181h.7z"/>
<path d="M20.2 193.7h2z"/>
<path d="M213.1 181h.7z"/>
<path d="M214.7 181h.8z"/>
<path d="M196 180.9l1.9 .1z"/>
<path d="M199 180.9l.8 .1z"/>
<path d="M201.3 180.9l1.2 .1z"/>
<path d="M203.5 180.9l1.8 .1z"/>
<path d="M206.1 180.9l1.2 .1z"/>
<path d="M208.9 180.9l.7 .1z"/>
<path d="M210.7 180.9l1.9 .1z"/>
<path d="M213 180.9l.8 .1z"/>
<path d="M214.6 180.9l.9 .1z"/>
<path d="M196 180.8l1.9 .1z"/>
<path d="M198.9 180.8l.9 .1z"/>
<path d="M201.2 180.8l1.4 .1z"/>
<path d="M203.5 180.8l1.8 .1z"/>
<path d="M206 180.8l1.4 .1z"/>
<path d="M208.9 180.8l.7 .1z"/>
<path d="M210.7 180.8l1.9 .1z"/>
<path d="M213 180.8l.8 .1z"/>
<path d="M214.6 180.8l.8 .1z"/>
<path d="M196 180.8h1.9z"/>
<path d="M198.9 180.8h1z"/>
<path d="M201.1 180.8h1.6z"/>
<path d="M203.5 180.8h1.8z"/>
<path d="M205.9 180.8h1.6z"/>
<path d="M208.9 180.8h.7z"/>
<path d="M210.7 180.8h1.9z"/>
<path d="M213 180.8h.8z"/>
<path d="M214.6 180.8h.8z"/>
<path d="M196 180.7l1.9 .1z"/>
<path d="M198.9 180.7l1 .1z"/>
<path d="M201 180.7l1.7 .1z"/>
<path d="M203.5 180.7l1.8 .1z"/>
<path d="M205.9 180.7l1.7 .1z"/>
<path d="M208.9 180.7l.7 .1z"/>
<path d="M210.7 180.7l1.9 .1z"/>
<path d="M213 180.7l.8 .1z"/>
<path d="M214.5 180.7l.9 .1z"/>
<path d="M196 180.7h1.9z"/>
<path d="M198.9 180.7h1z"/>
<path d="M201 180.7h1.8z"/>
<path d="M203.5 180.7h1.8z"/>
<path d="M205.8 180.7h1.8z"/>
<path d="M208.9 180.7h.7z"/>
<path d="M210.7 180.7h1.9z"/>
<path d="M213 180.7h.8z"/>
<path d="M214.5 180.7h.9z"/>
<path d="M217.3 180.7h.2z"/>
<path d="M219.4 180.7h.3z"/>
<path d="M214.5 180.7h.8z"/>
<path d="M217.2 180.7h.3z"/>
<path d="M219.3 180.7h.4z"/>
<path d="M196 180.6h1.9z"/>
<path d="M198.8 180.6h1.1z"/>
<path d="M200.9 180.6h2z"/>
<path d="M203.5 180.6h1.8z"/>
<path d="M205.7 180.6h2z"/>
<path d="M208.9 180.6h.7z"/>
<path d="M210.7 180.6h1.9z"/>
<path d="M213 180.6h.8z"/>
<path d="M214.5 180.6h.8z"/>
<path d="M217 180.6h.5z"/>
<path d="M219.2 180.6h.5z"/>
<path d="M214.4 180.6h.9z"/>
<path d="M216.9 180.6h.6z"/>
<path d="M219 180.6h.7z"/>
<path d="M196 180.5h1.9z"/>
<path d="M198.8 180.5h1.1z"/>
<path d="M200.9 180.5h.9z"/>
<path d="M201.9 180.5h1z"/>
<path d="M203.5 180.5h1.8z"/>
<path d="M205.7 180.5h2.1z"/>
<path d="M208.9 180.5h.7z"/>
<path d="M210.7 180.5h1.9z"/>
<path d="M213 180.5h.8z"/>
<path d="M214.4 180.5h.8z"/>
<path d="M216.7 180.5h.8z"/>
<path d="M218.9 180.5h.8z"/>
<path d="M196 180.4l.7 .1z"/>
<path d="M198.8 180.4l1.2 .1z"/>
<path d="M200.8 180.4l.8 .1z"/>
<path d="M202.1 180.4l.9 .1z"/>
<path d="M203.5 180.4l1.8 .1z"/>
<path d="M205.7 180.4l.8 .1z"/>
<path d="M206.9 180.4l.9 .1z"/>
<path d="M208.9 180.4l.7 .1z"/>
<path d="M210.7 180.4l.7 .1z"/>
<path d="M213 180.4l.8 .1z"/>
<path d="M214.4 180.4l.8 .1z"/>
<path d="M216.7 180.4l.8 .1z"/>
<path d="M218.8 180.4l.9 .1z"/>
<path d="M196 180.4h.7z"/>
<path d="M198.8 180.4h1.2z"/>
<path d="M200.8 180.4h.8z"/>
<path d="M202.2 180.4h.8z"/>
<path d="M203.5 180.4h.7z"/>
<path d="M205.6 180.4h.8z"/>
<path d="M207 180.4h.8z"/>
<path d="M208.9 180.4h.7z"/>
<path d="M210.7 180.4h.7z"/>
<path d="M213 180.4h.8z"/>
<path d="M214.3 180.4h.9z"/>
<path d="M216.5 180.4h1z"/>
<path d="M218.7 180.4h1z"/>
<path d="M196 180.3l.7 .1z"/>
<path d="M198.7 180.3l1.3 .1z"/>
<path d="M200.7 180.3l.8 .1z"/>
<path d="M202.3 180.3l.7 .1z"/>
<path d="M203.5 180.3l.7 .1z"/>
<path d="M205.6 180.3l.8 .1z"/>
<path d="M207.1 180.3l.7 .1z"/>
<path d="M208.9 180.3l.7 .1z"/>
<path d="M210.7 180.3l.7 .1z"/>
<path d="M213 180.3l.8 .1z"/>
<path d="M214.3 180.3l.8 .1z"/>
<path d="M216.4 180.3l1.1 .1z"/>
<path d="M218.5 180.3l1.2 .1z"/>
<path d="M196 180.3h.7z"/>
<path d="M198.7 180.3h1.3z"/>
<path d="M200.7 180.3h.8z"/>
<path d="M202.3 180.3h.7z"/>
<path d="M203.5 180.3h.7z"/>
<path d="M205.6 180.3h.7z"/>
<path d="M207.1 180.3h.7z"/>
<path d="M208.9 180.3h.7z"/>
<path d="M210.7 180.3h.7z"/>
<path d="M213 180.3h.9z"/>
<path d="M214.3 180.3h.8z"/>
<path d="M216.2 180.3h1.3z"/>
<path d="M218.4 180.3h1.3z"/>
<path d="M196 180.2l.7 .1z"/>
<path d="M198.7 180.2l.6 .1z"/>
<path d="M199.4 180.2l.6 .1z"/>
<path d="M200.7 180.2l.8 .1z"/>
<path d="M202.3 180.2l.7 .1z"/>
<path d="M203.5 180.2l.7 .1z"/>
<path d="M205.6 180.2l.7 .1z"/>
<path d="M207.1 180.2l.7 .1z"/>
<path d="M208.9 180.2l.7 .1z"/>
<path d="M210.7 180.2l.7 .1z"/>
<path d="M213 180.2l1 .1z"/>
<path d="M214.3 180.2l.8 .1z"/>
<path d="M216.1 180.2l1.3 .1z"/>
<path d="M218.3 180.2l1.3 .1z"/>
<path d="M196 180.2h.7z"/>
<path d="M198.7 180.2h.6z"/>
<path d="M199.4 180.2h.7z"/>
<path d="M200.7 180.2h.7z"/>
<path d="M202.3 180.2h.7z"/>
<path d="M203.5 180.2h.7z"/>
<path d="M205.6 180.2h.7z"/>
<path d="M207.1 180.2h.7z"/>
<path d="M208.9 180.2h.7z"/>
<path d="M210.7 180.2h.7z"/>
<path d="M213 180.2h1z"/>
<path d="M214.2 180.2h.8z"/>
<path d="M216 180.2h1.3z"/>
<path d="M218.1 180.2h1.4z"/>
<path d="M196 180.1l.7 .1z"/>
<path d="M198.7 180.1l.6 .1z"/>
<path d="M199.4 180.1l.7 .1z"/>
<path d="M200.7 180.1l.7 .1z"/>
<path d="M202.3 180.1l.8 .1z"/>
<path d="M203.5 180.1l.7 .1z"/>
<path d="M205.6 180.1l.7 .1z"/>
<path d="M207.1 180.1l.7 .1z"/>
<path d="M208.9 180.1l.7 .1z"/>
<path d="M210.7 180.1l.7 .1z"/>
<path d="M213 180.1l1.1 .1z"/>
<path d="M214.2 180.1l.8 .1z"/>
<path d="M215.8 180.1l1.3 .1z"/>
<path d="M218 180.1l1.3 .1z"/>
<path d="M196 180.1h.7z"/>
<path d="M198.6 180.1h.7z"/>
<path d="M199.5 180.1h.6z"/>
<path d="M200.7 180.1h.7z"/>
<path d="M202.4 180.1h.7z"/>
<path d="M203.5 180.1h.7z"/>
<path d="M205.6 180.1h.7z"/>
<path d="M207.1 180.1h.7z"/>
<path d="M208.9 180.1h.7z"/>
<path d="M210.7 180.1h.7z"/>
<path d="M213 180.1h1.1z"/>
<path d="M214.2 180.1h.8z"/>
<path d="M215.7 180.1h1.3z"/>
<path d="M217.9 180.1h1.3z"/>
<path d="M196 180l.7 .1z"/>
<path d="M198.6 180l.7 .1z"/>
<path d="M199.5 180l.7 .1z"/>
<path d="M200.7 180l.7 .1z"/>
<path d="M202.4 180l.7 .1z"/>
<path d="M203.5 180l.7 .1z"/>
<path d="M205.6 180l.7 .1z"/>
<path d="M207.1 180l.7 .1z"/>
<path d="M208.9 180l.7 .1z"/>
<path d="M210.7 180l.7 .1z"/>
<path d="M213 180l1.9 .1z"/>
<path d="M215.7 180l1.2 .1z"/>
<path d="M217.9 180l1.2 .1z"/>
<path d="M196 180h1.8z"/>
<path d="M198.6 180h.7z"/>
<path d="M199.5 180h.7z"/>
<path d="M200.7 180h.7z"/>
<path d="M202.4 180h.7z"/>
<path d="M203.5 180h.7z"/>
<path d="M205.6 180h.7z"/>
<path d="M207.1 180h.7z"/>
<path d="M208.9 180h.7z"/>
<path d="M210.7 180h1.8z"/>
<path d="M213 180h1.9z"/>
<path d="M215.7 180h1z"/>
<path d="M217.9 180h1z"/>
<path d="M196 179.9l1.8 .1z"/>
<path d="M198.6 179.9l.6 .1z"/>
<path d="M199.5 179.9l.6 .1z"/>
<path d="M200.7 179.9l.7 .1z"/>
<path d="M202.4 179.9l.7 .1z"/>
<path d="M203.5 179.9l.7 .1z"/>
<path d="M205.6 179.9l.7 .1z"/>
<path d="M207.1 179.9l.7 .1z"/>
<path d="M208.9 179.9l.7 .1z"/>
<path d="M210.7 179.9l1.8 .1z"/>
<path d="M213 179.9l1.9 .1z"/>
<path d="M215.8 179.9l.8 .1z"/>
<path d="M217.9 179.9l.9 .1z"/>
<path d="M196 179.9h1.8z"/>
<path d="M198.6 179.9h.6z"/>
<path d="M199.5 179.9h.7z"/>
<path d="M200.7 179.9h.7z"/>
<path d="M202.4 179.9h.7z"/>
<path d="M203.5 179.9h.7z"/>
<path d="M205.6 179.9h.7z"/>
<path d="M207.1 179.9h.7z"/>
<path d="M208.9 179.9h.7z"/>
<path d="M210.7 179.9h1.8z"/>
<path d="M213 179.9h1.8z"/>
<path d="M215.7 179.9h.8z"/>
<path d="M217.9 179.9h.7z"/>
<path d="M196 179.8l1.8 .1z"/>
<path d="M198.5 179.8l.7 .1z"/>
<path d="M199.5 179.8l.7 .1z"/>
<path d="M200.7 179.8l.7 .1z"/>
<path d="M202.4 179.8l.7 .1z"/>
<path d="M203.5 179.8l.7 .1z"/>
<path d="M205.6 179.8l.7 .1z"/>
<path d="M207.1 179.8l.7 .1z"/>
<path d="M208.9 179.8l.7 .1z"/>
<path d="M210.7 179.8l1.8 .1z"/>
<path d="M213 179.8l1.8 .1z"/>
<path d="M215.7 179.8l.8 .1z"/>
<path d="M217.9 179.8l.7 .1z"/>
<path d="M196 179.8h1.8z"/>
<path d="M198.5 179.8h.7z"/>
<path d="M199.6 179.8h.7z"/>
<path d="M200.7 179.8h.7z"/>
<path d="M202.4 179.8h.7z"/>
<path d="M203.5 179.8h.7z"/>
<path d="M205.6 179.8h.7z"/>
<path d="M207.1 179.8h.7z"/>
<path d="M208.9 179.8h.7z"/>
<path d="M210.7 179.8h1.8z"/>
<path d="M213 179.8h1.8z"/>
<path d="M215.7 179.8h1z"/>
<path d="M217.9 179.8h.9z"/>
<path d="M196 179.7l1.8 .1z"/>
<path d="M198.5 179.7l.7 .1z"/>
<path d="M199.6 179.7l.7 .1z"/>
<path d="M200.7 179.7l.7 .1z"/>
<path d="M202.4 179.7l.7 .1z"/>
<path d="M203.5 179.7l.7 .1z"/>
<path d="M205.6 179.7l.7 .1z"/>
<path d="M207.1 179.7l.7 .1z"/>
<path d="M208.9 179.7l.7 .1z"/>
<path d="M210.7 179.7l1.8 .1z"/>
<path d="M213 179.7l1.7 .1z"/>
<path d="M215.7 179.7l1 .1z"/>
<path d="M217.9 179.7l1 .1z"/>
<path d="M196 179.7h1.8z"/>
<path d="M198.5 179.7h.7z"/>
<path d="M199.6 179.7h.7z"/>
<path d="M200.7 179.7h.7z"/>
<path d="M202.4 179.7h.7z"/>
<path d="M203.5 179.7h.7z"/>
<path d="M205.6 179.7h.7z"/>
<path d="M207.1 179.7h.7z"/>
<path d="M208.9 179.7h.7z"/>
<path d="M210.7 179.7h1.8z"/>
<path d="M213 179.7h1.7z"/>
<path d="M215.7 179.7h1.2z"/>
<path d="M217.9 179.7h1.2z"/>
<path d="M196 179.6l1.8 .1z"/>
<path d="M198.5 179.6l.6 .1z"/>
<path d="M199.6 179.6l.7 .1z"/>
<path d="M200.7 179.6l.7 .1z"/>
<path d="M202.4 179.6l.7 .1z"/>
<path d="M203.5 179.6l.7 .1z"/>
<path d="M205.6 179.6l.7 .1z"/>
<path d="M207.1 179.6l.7 .1z"/>
<path d="M208.9 179.6l.7 .1z"/>
<path d="M210.7 179.6l1.8 .1z"/>
<path d="M213 179.6l1.7 .1z"/>
<path d="M215.7 179.6l1.3 .1z"/>
<path d="M217.9 179.6l1.3 .1z"/>
<path d="M196 179.6h.7z"/>
<path d="M198.4 179.6h.7z"/>
<path d="M199.6 179.6h.7z"/>
<path d="M200.7 179.6h.7z"/>
<path d="M202.3 179.6h.8z"/>
<path d="M203.5 179.6h.7z"/>
<path d="M205.6 179.6h.7z"/>
<path d="M207.1 179.6h.7z"/>
<path d="M208.9 179.6h.7z"/>
<path d="M210.7 179.6h.7z"/>
<path d="M213 179.6h1.7z"/>
<path d="M215.8 179.6h1.4z"/>
<path d="M218 179.6h1.3z"/>
<path d="M196 179.5l.7 .1z"/>
<path d="M198.4 179.5l.7 .1z"/>
<path d="M199.6 179.5l.7 .1z"/>
<path d="M200.7 179.5l.7 .1z"/>
<path d="M202.3 179.5l.7 .1z"/>
<path d="M203.5 179.5l.7 .1z"/>
<path d="M205.6 179.5l.7 .1z"/>
<path d="M207.1 179.5l.7 .1z"/>
<path d="M208.9 179.5l.7 .1z"/>
<path d="M210.7 179.5l.7 .1z"/>
<path d="M213 179.5l.8 .1z"/>
<path d="M213.9 179.5l.8 .1z"/>
<path d="M216 179.5l1.3 .1z"/>
<path d="M218.2 179.5l1.3 .1z"/>
<path d="M196 179.5h.7z"/>
<path d="M198.4 179.5h.7z"/>
<path d="M199.7 179.5h.7z"/>
<path d="M200.7 179.5h.8z"/>
<path d="M202.3 179.5h.7z"/>
<path d="M203.5 179.5h.7z"/>
<path d="M205.6 179.5h.7z"/>
<path d="M207.1 179.5h.7z"/>
<path d="M208.9 179.5h.7z"/>
<path d="M210.7 179.5h.7z"/>
<path d="M213 179.5h.8z"/>
<path d="M213.9 179.5h.9z"/>
<path d="M216.2 179.5h1.3z"/>
<path d="M218.3 179.5h1.3z"/>
<path d="M196 179.4l.7 .1z"/>
<path d="M198.4 179.4l.7 .1z"/>
<path d="M199.7 179.4l.7 .1z"/>
<path d="M200.7 179.4l.8 .1z"/>
<path d="M202.3 179.4l.7 .1z"/>
<path d="M203.5 179.4l.7 .1z"/>
<path d="M205.6 179.4l.7 .1z"/>
<path d="M207.1 179.4l.7 .1z"/>
<path d="M208.9 179.4l.7 .1z"/>
<path d="M210.7 179.4l.7 .1z"/>
<path d="M213 179.4l.8 .1z"/>
<path d="M213.9 179.4l.9 .1z"/>
<path d="M216.2 179.4l1.3 .1z"/>
<path d="M218.4 179.4l1.3 .1z"/>
<path d="M196 179.4h.7z"/>
<path d="M198.4 179.4h.7z"/>
<path d="M199.7 179.4h.7z"/>
<path d="M200.7 179.4h.8z"/>
<path d="M202.2 179.4h.8z"/>
<path d="M203.5 179.4h.7z"/>
<path d="M205.6 179.4h.7z"/>
<path d="M207.1 179.4h.7z"/>
<path d="M208.9 179.4h.7z"/>
<path d="M210.7 179.4h.7z"/>
<path d="M213 179.4h.8z"/>
<path d="M214 179.4h.9z"/>
<path d="M216.4 179.4h1.1z"/>
<path d="M218.5 179.4h1.2z"/>
<path d="M196 179.3l.7 .1z"/>
<path d="M198.3 179.3l.7 .1z"/>
<path d="M199.7 179.3l.7 .1z"/>
<path d="M200.8 179.3l.8 .1z"/>
<path d="M202.2 179.3l.8 .1z"/>
<path d="M203.5 179.3l.7 .1z"/>
<path d="M205.6 179.3l.7 .1z"/>
<path d="M207.1 179.3l.7 .1z"/>
<path d="M208.9 179.3l.7 .1z"/>
<path d="M210.7 179.3l.7 .1z"/>
<path d="M213 179.3l.8 .1z"/>
<path d="M214 179.3l.9 .1z"/>
<path d="M216.5 179.3l1 .1z"/>
<path d="M218.7 179.3l1 .1z"/>
<path d="M196 179.3h.7z"/>
<path d="M198.3 179.3h.7z"/>
<path d="M199.7 179.3h.7z"/>
<path d="M200.8 179.3h.9z"/>
<path d="M202.1 179.3h.9z"/>
<path d="M203.5 179.3h.7z"/>
<path d="M205.6 179.3h.7z"/>
<path d="M207.1 179.3h.7z"/>
<path d="M208.2 179.3h2.2z"/>
<path d="M210.7 179.3h.7z"/>
<path d="M213 179.3h.8z"/>
<path d="M214.1 179.3h.9z"/>
<path d="M216.7 179.3h.8z"/>
<path d="M218.8 179.3h.9z"/>
<path d="M196 179.2l1.8 .1z"/>
<path d="M198.3 179.2l.7 .1z"/>
<path d="M199.7 179.2l.7 .1z"/>
<path d="M200.9 179.2l2 .1z"/>
<path d="M203.5 179.2l.7 .1z"/>
<path d="M205.6 179.2l.7 .1z"/>
<path d="M207.1 179.2l.7 .1z"/>
<path d="M208.2 179.2l2.2 .1z"/>
<path d="M210.7 179.2l1.9 .1z"/>
<path d="M213 179.2l.8 .1z"/>
<path d="M214.1 179.2l.9 .1z"/>
<path d="M216.8 179.2l.7 .1z"/>
<path d="M218.9 179.2l.8 .1z"/>
<path d="M196 179.2h1.9z"/>
<path d="M198.3 179.2h.7z"/>
<path d="M199.8 179.2h.6z"/>
<path d="M200.9 179.2h2z"/>
<path d="M203.5 179.2h.7z"/>
<path d="M205.6 179.2h.7z"/>
<path d="M207.1 179.2h.7z"/>
<path d="M208.2 179.2h2.2z"/>
<path d="M210.7 179.2h1.9z"/>
<path d="M213 179.2h.8z"/>
<path d="M214.1 179.2h1z"/>
<path d="M216.9 179.2h.6z"/>
<path d="M219.1 179.2h.6z"/>
<path d="M196 179.1l1.9 .1z"/>
<path d="M198.3 179.1l.7 .1z"/>
<path d="M199.8 179.1l.7 .1z"/>
<path d="M200.9 179.1l2 .1z"/>
<path d="M203.5 179.1l.7 .1z"/>
<path d="M205.6 179.1l.7 .1z"/>
<path d="M207.1 179.1l.7 .1z"/>
<path d="M208.2 179.1l2.2 .1z"/>
<path d="M210.7 179.1l1.9 .1z"/>
<path d="M213 179.1l.8 .1z"/>
<path d="M214.2 179.1l.9 .1z"/>
<path d="M217 179.1l.5 .1z"/>
<path d="M219.2 179.1l.5 .1z"/>
<path d="M196 179.1h1.9z"/>
<path d="M198.2 179.1h.8z"/>
<path d="M199.8 179.1h.7z"/>
<path d="M201 179.1h1.8z"/>
<path d="M203.5 179.1h.7z"/>
<path d="M205.6 179.1h.7z"/>
<path d="M207.1 179.1h.7z"/>
<path d="M208.2 179.1h2.2z"/>
<path d="M210.7 179.1h1.9z"/>
<path d="M213 179.1h.8z"/>
<path d="M214.2 179.1h1z"/>
<path d="M217.2 179.1h.3z"/>
<path d="M219.4 179.1h.3z"/>
<path d="M196 179l1.9 .1z"/>
<path d="M198.2 179l.7 .1z"/>
<path d="M199.8 179l.8 .1z"/>
<path d="M201 179l1.8 .1z"/>
<path d="M203.5 179l.7 .1z"/>
<path d="M205.6 179l.7 .1z"/>
<path d="M207.1 179l.7 .1z"/>
<path d="M208.2 179l2.2 .1z"/>
<path d="M210.7 179l1.9 .1z"/>
<path d="M213 179l.8 .1z"/>
<path d="M214.3 179l.9 .1z"/>
<path d="M217.3 179l.2 .1z"/>
<path d="M219.4 179l.3 .1z"/>
<path d="M196 179h1.9z"/>
<path d="M198.2 179h.7z"/>
<path d="M199.8 179h.8z"/>
<path d="M201 179h1.7z"/>
<path d="M203.5 179h.7z"/>
<path d="M205.6 179h.7z"/>
<path d="M207.1 179h.7z"/>
<path d="M208.2 179h2.2z"/>
<path d="M210.7 179h1.9z"/>
<path d="M213 179h.8z"/>
<path d="M214.4 179h.9z"/>
<path d="M196 178.9l1.9 .1z"/>
<path d="M198.2 178.9l.7 .1z"/>
<path d="M199.8 178.9l.8 .1z"/>
<path d="M201.1 178.9l1.5 .1z"/>
<path d="M203.5 178.9l.7 .1z"/>
<path d="M205.6 178.9l.7 .1z"/>
<path d="M207.1 178.9l.7 .1z"/>
<path d="M208.2 178.9l2.2 .1z"/>
<path d="M210.7 178.9l1.9 .1z"/>
<path d="M213 178.9l.8 .1z"/>
<path d="M214.4 178.9l.9 .1z"/>
<path d="M196 178.9h1.9z"/>
<path d="M198.2 178.9h.7z"/>
<path d="M199.9 178.9h.7z"/>
<path d="M201.2 178.9h1.4z"/>
<path d="M203.5 178.9h.7z"/>
<path d="M205.6 178.9h.7z"/>
<path d="M207.1 178.9h.7z"/>
<path d="M208.2 178.9h2.2z"/>
<path d="M210.7 178.9h1.9z"/>
<path d="M213 178.9h.8z"/>
<path d="M214.4 178.9h1z"/>
<path d="M196 178.8l1.9 .1z"/>
<path d="M198.1 178.8l.8 .1z"/>
<path d="M199.9 178.8l.7 .1z"/>
<path d="M201.3 178.8l1.1 .1z"/>
<path d="M203.5 178.8l.7 .1z"/>
<path d="M205.6 178.8l.7 .1z"/>
<path d="M207.1 178.8l.7 .1z"/>
<path d="M208.2 178.8l2.2 .1z"/>
<path d="M210.7 178.8l1.9 .1z"/>
<path d="M213 178.8l.8 .1z"/>
<path d="M214.5 178.8l.9 .1z"/>
<path d="M196 178.8h1.8z"/>
<path d="M198.1 178.8h.7z"/>
<path d="M199.9 178.8h.7z"/>
<path d="M201.5 178.8h.8z"/>
<path d="M203.5 178.8h.7z"/>
<path d="M205.6 178.8h.7z"/>
<path d="M207.1 178.8h.7z"/>
<path d="M208.2 178.8h2.2z"/>
<path d="M210.7 178.8h1.9z"/>
<path d="M213.1 178.8h.7z"/>
<path d="M214.5 178.8h.9z"/>
<path d="M195.9 178.6h23.7z"/>
<path d="M196 178.5l23.6 .1z"/>
<path d="M214 178.4h.5z"/>
<path d="M215.1 178.4h1.2z"/>
<path d="M209 178.3l.3 .1z"/>
<path d="M209.7 178.3l.3 .1z"/>
<path d="M213.1 178.3l.5 .1z"/>
<path d="M213.8 178.3l.7 .1z"/>
<path d="M215 178.3l1.3 .1z"/>
<path d="M208.5 178.3h.2z"/>
<path d="M208.9 178.3h.9z"/>
<path d="M213.1 178.3h1.4z"/>
<path d="M215 178.3h.2z"/>
<path d="M205.3 178.2h1.3z"/>
<path d="M207.6 178.2h.4z"/>
<path d="M208.1 178.2h.4z"/>
<path d="M208.9 178.2h.7z"/>
<path d="M213.1 178.2h1.4z"/>
<path d="M197.5 178.2h1.1z"/>
<path d="M202 178.2h.4z"/>
<path d="M205.2 178.2h.8z"/>
<path d="M207.6 178.2h.8z"/>
<path d="M208.9 178.2h.2z"/>
<path d="M213.1 178.2h1.3z"/>
<path d="M196.6 178.1l.5 .1z"/>
<path d="M197.5 178.1l1.1 .1z"/>
<path d="M199.1 178.1l.4 .1z"/>
<path d="M202 178.1l.4 .1z"/>
<path d="M204 178.1l.3 .1z"/>
<path d="M205.2 178.1l.5 .1z"/>
<path d="M207.6 178.1l.3 .1z"/>
<path d="M208 178.1l.2 .1z"/>
<path d="M208.9 178.1l.2 .1z"/>
<path d="M211.1 178.1l.4 .1z"/>
<path d="M213.2 178.1l1 .1z"/>
<path d="M196.6 178.1h.4z"/>
<path d="M197.5 178.1h.2z"/>
<path d="M199.1 178.1h.3z"/>
<path d="M200.7 178.1h.3z"/>
<path d="M202 178.1h.2z"/>
<path d="M204 178.1h.2z"/>
<path d="M205.2 178.1h.4z"/>
<path d="M207.6 178.1h.2z"/>
<path d="M208.9 178.1h.2z"/>
<path d="M211 178.1h.5z"/>
<path d="M213.2 178.1h.9z"/>
<path d="M215 178.1h.2z"/>
<path d="M196.5 178l.2 .1z"/>
<path d="M197.5 178l.2 .1z"/>
<path d="M199.2 178l.2 .1z"/>
<path d="M200.6 178l.5 .1z"/>
<path d="M203.9 178l.2 .1z"/>
<path d="M205.3 178l.2 .1z"/>
<path d="M207.6 178l.2 .1z"/>
<path d="M208.9 178l.2 .1z"/>
<path d="M211 178l.5 .1z"/>
<path d="M213.2 178l.8 .1z"/>
<path d="M215.1 178l.1 .1z"/>
<path d="M196.5 177.9l.2 .1z"/>
<path d="M197.5 177.9l.2 .1z"/>
<path d="M199.2 177.9l.2 .1z"/>
<path d="M200.7 177.9l.3 .1z"/>
<path d="M202 177.9l.2 .1z"/>
<path d="M205.3 177.9l.2 .1z"/>
<path d="M207.6 177.9l.3 .1z"/>
<path d="M208.9 177.9l.3 .1z"/>
<path d="M211 177.9l.5 .1z"/>
<path d="M213.3 177.9l.5 .1z"/>
<path d="M215.1 177.9l.1 .1z"/>
<path d="M196.4 177.9h.2z"/>
<path d="M197.5 177.9h.2z"/>
<path d="M200.7 177.9h.2z"/>
<path d="M203.8 177.9h.2z"/>
<path d="M205.3 177.9h.2z"/>
<path d="M207.7 177.9h.2z"/>
<path d="M209 177.9h.2z"/>
<path d="M210.9 177.9h.4z"/>
<path d="M213.2 177.9h.5z"/>
<path d="M215.1 177.9h.2z"/>
<path d="M202.1 177.9h.2z"/>
<path d="M203.7 177.9h.2z"/>
<path d="M205.4 177.9h.2z"/>
<path d="M210.8 177.9h.5z"/>
<path d="M196.4 177.8h.2z"/>
<path d="M197.5 177.8h.2z"/>
<path d="M200.7 177.8h.2z"/>
<path d="M202.1 177.8h.2z"/>
<path d="M203.7 177.8h.2z"/>
<path d="M205.4 177.8h.2z"/>
<path d="M207.7 177.8h.2z"/>
<path d="M209 177.8h.2z"/>
<path d="M210.8 177.8h.5z"/>
<path d="M213.2 177.8h.5z"/>
<path d="M196.3 177.8h.2z"/>
<path d="M200.7 177.8h.3z"/>
<path d="M203.6 177.8h.2z"/>
<path d="M205.4 177.8h.1z"/>
<path d="M210.8 177.8h.4z"/>
<path d="M213.1 177.8h.5z"/>
<path d="M215.1 177.8h.2z"/>
<path d="M196.3 177.7h.2z"/>
<path d="M197.5 177.7h.2z"/>
<path d="M200.8 177.7h.2z"/>
<path d="M202.1 177.7h.2z"/>
<path d="M203.5 177.7h.3z"/>
<path d="M205.4 177.7h.2z"/>
<path d="M207.7 177.7h.2z"/>
<path d="M209 177.7h.2z"/>
<path d="M210.5 177.7h.7z"/>
<path d="M213.1 177.7h.5z"/>
<path d="M215.1 177.7h.2z"/>
<path d="M196.2 177.7h.3z"/>
<path d="M202.1 177.7h.1z"/>
<path d="M203.4 177.7h.3z"/>
<path d="M207.6 177.7h.3z"/>
<path d="M208.9 177.7h.2z"/>
<path d="M210.6 177.7h.6z"/>
<path d="M215.1 177.7h.1z"/>
<path d="M196.2 177.6l.3 .1z"/>
<path d="M197.5 177.6l.2 .1z"/>
<path d="M200.8 177.6l.2 .1z"/>
<path d="M202 177.6l.2 .1z"/>
<path d="M203.4 177.6l.3 .1z"/>
<path d="M205.4 177.6l.2 .1z"/>
<path d="M207.6 177.6l.3 .1z"/>
<path d="M208.9 177.6l.2 .1z"/>
<path d="M210.5 177.6l.7 .1z"/>
<path d="M213.1 177.6l.5 .1z"/>
<path d="M215.1 177.6l.1 .1z"/>
<path d="M196.3 177.5l.2 .1z"/>
<path d="M197.5 177.5l.2 .1z"/>
<path d="M200.9 177.5l.1 .1z"/>
<path d="M202 177.5l.2 .1z"/>
<path d="M203.5 177.5l.3 .1z"/>
<path d="M205.3 177.5l.3 .1z"/>
<path d="M207.6 177.5l.3 .1z"/>
<path d="M208.9 177.5l.2 .1z"/>
<path d="M210.5 177.5l.6 .1z"/>
<path d="M213.1 177.5l.5 .1z"/>
<path d="M215.1 177.5l.1 .1z"/>
<path d="M196.3 177.5h.3z"/>
<path d="M197.5 177.5h.2z"/>
<path d="M200.9 177.5h.2z"/>
<path d="M202 177.5h.2z"/>
<path d="M203.5 177.5h.3z"/>
<path d="M205.3 177.5h.3z"/>
<path d="M207.6 177.5h.3z"/>
<path d="M208.9 177.5h.2z"/>
<path d="M210.4 177.5h.7z"/>
<path d="M211.2 177.5h.2z"/>
<path d="M213.1 177.5h.5z"/>
<path d="M215.1 177.5h.1z"/>
<path d="M196.4 177.4l.2 .1z"/>
<path d="M197.5 177.4l.2 .1z"/>
<path d="M200.9 177.4l.2 .1z"/>
<path d="M202 177.4l.2 .1z"/>
<path d="M203.5 177.4l.3 .1z"/>
<path d="M205.3 177.4l.3 .1z"/>
<path d="M207.6 177.4l.3 .1z"/>
<path d="M208.9 177.4l.2 .1z"/>
<path d="M210.4 177.4l1 .1z"/>
<path d="M213.1 177.4l.6 .1z"/>
<path d="M215 177.4l.2 .1z"/>
<path d="M196.4 177.4h.3z"/>
<path d="M197.5 177.4h.2z"/>
<path d="M199.7 177.4h.4z"/>
<path d="M200.9 177.4h.2z"/>
<path d="M202 177.4h.2z"/>
<path d="M203.6 177.4h.3z"/>
<path d="M205.3 177.4h.2z"/>
<path d="M207.6 177.4h.3z"/>
<path d="M208.8 177.4h.3z"/>
<path d="M210.5 177.4h.9z"/>
<path d="M213.1 177.4h.6z"/>
<path d="M215 177.4h.2z"/>
<path d="M196.5 177.4h.3z"/>
<path d="M199.1 177.4h.1z"/>
<path d="M199.7 177.4h.2z"/>
<path d="M208.8 177.4h.2z"/>
<path d="M210.6 177.4h.9z"/>
<path d="M213.1 177.4h.5z"/>
<path d="M196.5 177.3h.3z"/>
<path d="M197.5 177.3h.2z"/>
<path d="M199 177.3h.2z"/>
<path d="M199.7 177.3h.2z"/>
<path d="M200.9 177.3h.2z"/>
<path d="M202 177.3h.1z"/>
<path d="M203.7 177.3h.2z"/>
<path d="M205.3 177.3h.2z"/>
<path d="M207.6 177.3h.2z"/>
<path d="M208.8 177.3h.2z"/>
<path d="M210.7 177.3h.8z"/>
<path d="M213.1 177.3h.5z"/>
<path d="M215 177.3h.2z"/>
<path d="M196.6 177.2l.3 .1z"/>
<path d="M197.5 177.2l.2 .1z"/>
<path d="M199 177.2l.1 .1z"/>
<path d="M200.9 177.2l.2 .1z"/>
<path d="M201.9 177.2l.2 .1z"/>
<path d="M203.8 177.2l.2 .1z"/>
<path d="M205.3 177.2l.2 .1z"/>
<path d="M207.6 177.2l.2 .1z"/>
<path d="M208.8 177.2l.2 .1z"/>
<path d="M210.8 177.2l.8 .1z"/>
<path d="M213.1 177.2l.6 .1z"/>
<path d="M215 177.2l.2 .1z"/>
<path d="M196.6 177.2h.3z"/>
<path d="M197.5 177.2h.2z"/>
<path d="M198.9 177.2h.2z"/>
<path d="M200.9 177.2h.2z"/>
<path d="M201.9 177.2h.2z"/>
<path d="M203.8 177.2h.2z"/>
<path d="M205.3 177.2h.2z"/>
<path d="M207.6 177.2h.2z"/>
<path d="M208.7 177.2h.3z"/>
<path d="M210.7 177.2h.9z"/>
<path d="M213.1 177.2h.6z"/>
<path d="M215 177.2h.2z"/>
<path d="M196.7 177.1l.3 .1z"/>
<path d="M197.5 177.1l.2 .1z"/>
<path d="M198.9 177.1l.1 .1z"/>
<path d="M200.9 177.1l.2 .1z"/>
<path d="M201.9 177.1l.2 .1z"/>
<path d="M203.8 177.1l.2 .1z"/>
<path d="M205.3 177.1l.2 .1z"/>
<path d="M207.6 177.1l.2 .1z"/>
<path d="M208.7 177.1l.3 .1z"/>
<path d="M210.8 177.1l.8 .1z"/>
<path d="M213.1 177.1l.6 .1z"/>
<path d="M215 177.1l.2 .1z"/>
<path d="M196.8 177.1h.2z"/>
<path d="M197.5 177.1h.2z"/>
<path d="M198.8 177.1h.2z"/>
<path d="M200.9 177.1h.2z"/>
<path d="M201.9 177.1h.2z"/>
<path d="M203.8 177.1h.2z"/>
<path d="M205.3 177.1h.2z"/>
<path d="M207.6 177.1h.2z"/>
<path d="M208.7 177.1h.2z"/>
<path d="M210.8 177.1h.9z"/>
<path d="M213.1 177.1h.5z"/>
<path d="M215 177.1h.2z"/>
<path d="M196.8 177l.3 .1z"/>
<path d="M197.4 177l.3 .1z"/>
<path d="M198.8 177l.1 .1z"/>
<path d="M200.9 177l.2 .1z"/>
<path d="M201.9 177l.2 .1z"/>
<path d="M203.9 177l.2 .1z"/>
<path d="M205.3 177l.2 .1z"/>
<path d="M207.6 177l.2 .1z"/>
<path d="M208.7 177l.2 .1z"/>
<path d="M210.8 177l.9 .1z"/>
<path d="M213.1 177l.5 .1z"/>
<path d="M215 177l.2 .1z"/>
<path d="M196.8 177h.9z"/>
<path d="M198.7 177h.2z"/>
<path d="M199.6 177h.1z"/>
<path d="M200.9 177h.2z"/>
<path d="M201.9 177h.2z"/>
<path d="M203.9 177h.2z"/>
<path d="M205.3 177h.2z"/>
<path d="M207.6 177h.2z"/>
<path d="M208.7 177h.2z"/>
<path d="M210.8 177h1z"/>
<path d="M213.1 177h.5z"/>
<path d="M215 177h.2z"/>
<path d="M196.8 176.9l.7 .1z"/>
<path d="M198.7 176.9l.1 .1z"/>
<path d="M199.5 176.9l.2 .1z"/>
<path d="M200.9 176.9l.2 .1z"/>
<path d="M201.9 176.9l.1 .1z"/>
<path d="M203.9 176.9l.2 .1z"/>
<path d="M205.3 176.9l.2 .1z"/>
<path d="M207.6 176.9l.2 .1z"/>
<path d="M208.7 176.9l.2 .1z"/>
<path d="M210.9 176.9l.9 .1z"/>
<path d="M213.1 176.9l.6 .1z"/>
<path d="M215 176.9l.2 .1z"/>
<path d="M196.8 176.9h.6z"/>
<path d="M198.6 176.9h.2z"/>
<path d="M199.4 176.9h.2z"/>
<path d="M200.9 176.9h.2z"/>
<path d="M201.9 176.9h.1z"/>
<path d="M203.9 176.9h.2z"/>
<path d="M205.3 176.9h.2z"/>
<path d="M207.6 176.9h.2z"/>
<path d="M208.7 176.9h.2z"/>
<path d="M211 176.9h.8z"/>
<path d="M213 176.9h.6z"/>
<path d="M215 176.9h.2z"/>
<path d="M196.8 176.8l.5 .1z"/>
<path d="M198.6 176.8l.1 .1z"/>
<path d="M199.1 176.8l.5 .1z"/>
<path d="M200.9 176.8l.2 .1z"/>
<path d="M201.9 176.8l.1 .1z"/>
<path d="M203.9 176.8l.3 .1z"/>
<path d="M205.3 176.8l.2 .1z"/>
<path d="M207.6 176.8l.2 .1z"/>
<path d="M208.7 176.8l.2 .1z"/>
<path d="M210.9 176.8l1 .1z"/>
<path d="M213 176.8l.6 .1z"/>
<path d="M215 176.8l.2 .1z"/>
<path d="M196.7 176.8h.6z"/>
<path d="M198.5 176.8h.2z"/>
<path d="M199.1 176.8h.4z"/>
<path d="M200.9 176.8h.2z"/>
<path d="M201.9 176.8h.1z"/>
<path d="M203.9 176.8h.3z"/>
<path d="M205.3 176.8h.3z"/>
<path d="M207.6 176.8h.2z"/>
<path d="M208.7 176.8h.2z"/>
<path d="M211 176.8h.9z"/>
<path d="M213 176.8h.6z"/>
<path d="M215 176.8h.2z"/>
<path d="M196.6 176.7l.5 .1z"/>
<path d="M198.5 176.7l.1 .1z"/>
<path d="M199.1 176.7l.3 .1z"/>
<path d="M200.9 176.7l.2 .1z"/>
<path d="M201.9 176.7l.1 .1z"/>
<path d="M204 176.7l.3 .1z"/>
<path d="M205.3 176.7l.3 .1z"/>
<path d="M207.6 176.7l.2 .1z"/>
<path d="M208.7 176.7l.2 .1z"/>
<path d="M211.1 176.7l.8 .1z"/>
<path d="M213 176.7l.6 .1z"/>
<path d="M215 176.7l.2 .1z"/>
<path d="M196.6 176.7h.4z"/>
<path d="M198.4 176.7h.2z"/>
<path d="M200.9 176.7h.3z"/>
<path d="M201.9 176.7h.1z"/>
<path d="M204 176.7h.3z"/>
<path d="M205.4 176.7h.2z"/>
<path d="M207.6 176.7h.3z"/>
<path d="M208.7 176.7h.2z"/>
<path d="M211.1 176.7h.9z"/>
<path d="M213 176.7h.6z"/>
<path d="M215 176.7h.2z"/>
<path d="M196.6 176.6l.3 .1z"/>
<path d="M198.4 176.6l.2 .1z"/>
<path d="M201 176.6l.2 .1z"/>
<path d="M201.9 176.6l.1 .1z"/>
<path d="M204 176.6l.5 .1z"/>
<path d="M205.4 176.6l.3 .1z"/>
<path d="M207.7 176.6l.2 .1z"/>
<path d="M208.7 176.6l.2 .1z"/>
<path d="M211.2 176.6l.8 .1z"/>
<path d="M213 176.6l.6 .1z"/>
<path d="M215 176.6l.2 .1z"/>
<path d="M196.5 176.6h.3z"/>
<path d="M198.4 176.6h.2z"/>
<path d="M201 176.6h.3z"/>
<path d="M201.9 176.6h.1z"/>
<path d="M204.1 176.6h.5z"/>
<path d="M205.4 176.6h.3z"/>
<path d="M207.7 176.6h.2z"/>
<path d="M208.7 176.6h.2z"/>
<path d="M211.2 176.6h.9z"/>
<path d="M213 176.6h.6z"/>
<path d="M215 176.6h.2z"/>
<path d="M196.5 176.5l.3 .1z"/>
<path d="M198.4 176.5l.2 .1z"/>
<path d="M201 176.5l.3 .1z"/>
<path d="M201.9 176.5l.2 .1z"/>
<path d="M204.2 176.5l.5 .1z"/>
<path d="M205.4 176.5l.3 .1z"/>
<path d="M207.7 176.5l.3 .1z"/>
<path d="M208.7 176.5l.2 .1z"/>
<path d="M211.2 176.5l.9 .1z"/>
<path d="M213 176.5l.6 .1z"/>
<path d="M215 176.5l.2 .1z"/>
<path d="M196.5 176.5h.2z"/>
<path d="M201.1 176.5h.3z"/>
<path d="M201.6 176.5h.2z"/>
<path d="M201.9 176.5h.2z"/>
<path d="M204.3 176.5h.5z"/>
<path d="M205.4 176.5h.3z"/>
<path d="M207.8 176.5h.2z"/>
<path d="M208.7 176.5h.2z"/>
<path d="M211.3 176.5h.6z"/>
<path d="M213 176.5h.6z"/>
<path d="M215 176.5h.2z"/>
<path d="M196.5 176.4l.2 .1z"/>
<path d="M201.1 176.4l.7 .1z"/>
<path d="M201.9 176.4l.2 .1z"/>
<path d="M204.3 176.4l.6 .1z"/>
<path d="M205.5 176.4l.2 .1z"/>
<path d="M207.8 176.4l.3 .1z"/>
<path d="M208.7 176.4l.2 .1z"/>
<path d="M211.3 176.4l.7 .1z"/>
<path d="M213 176.4l.6 .1z"/>
<path d="M215 176.4l.2 .1z"/>
<path d="M196.5 176.4h.2z"/>
<path d="M201.1 176.4h1z"/>
<path d="M204.4 176.4h.6z"/>
<path d="M205.5 176.4h.3z"/>
<path d="M207.8 176.4h.4z"/>
<path d="M208.7 176.4h.2z"/>
<path d="M211.3 176.4h.7z"/>
<path d="M213 176.4h.6z"/>
<path d="M215 176.4h.2z"/>
<path d="M196.5 176.3l.2 .1z"/>
<path d="M201.2 176.3l.9 .1z"/>
<path d="M204.4 176.3l.8 .1z"/>
<path d="M205.5 176.3l.3 .1z"/>
<path d="M207.8 176.3l.5 .1z"/>
<path d="M208.7 176.3l.2 .1z"/>
<path d="M211.4 176.3l.7 .1z"/>
<path d="M213 176.3l.6 .1z"/>
<path d="M215 176.3l.2 .1z"/>
<path d="M215.5 176.3l.1 .1z"/>
<path d="M196.5 176.3h.2z"/>
<path d="M201.2 176.3h.9z"/>
<path d="M204.5 176.3h.7z"/>
<path d="M205.4 176.3h.4z"/>
<path d="M207.8 176.3h.5z"/>
<path d="M208.7 176.3h.2z"/>
<path d="M211.4 176.3h.7z"/>
<path d="M213 176.3h.6z"/>
<path d="M215 176.3h.2z"/>
<path d="M196.5 176.2l.2 .1z"/>
<path d="M201.2 176.2l.9 .1z"/>
<path d="M204.6 176.2l.6 .1z"/>
<path d="M205.4 176.2l.4 .1z"/>
<path d="M207.9 176.2l.6 .1z"/>
<path d="M208.7 176.2l.2 .1z"/>
<path d="M211.5 176.2l.6 .1z"/>
<path d="M213 176.2l.6 .1z"/>
<path d="M215 176.2l.2 .1z"/>
<path d="M196.5 176.2h.2z"/>
<path d="M201.2 176.2h.9z"/>
<path d="M204.6 176.2h.6z"/>
<path d="M205.4 176.2h.3z"/>
<path d="M207.9 176.2h.6z"/>
<path d="M208.7 176.2h.2z"/>
<path d="M211.5 176.2h.6z"/>
<path d="M213 176.2h.6z"/>
<path d="M215 176.2h.4z"/>
<path d="M196.5 176.1l.2 .1z"/>
<path d="M201.2 176.1l.7 .1z"/>
<path d="M204.6 176.1l.6 .1z"/>
<path d="M205.4 176.1l.3 .1z"/>
<path d="M207.9 176.1l.6 .1z"/>
<path d="M208.6 176.1l.3 .1z"/>
<path d="M211.6 176.1l.5 .1z"/>
<path d="M213 176.1l.6 .1z"/>
<path d="M215.1 176.1l.4 .1z"/>
<path d="M196.5 176.1h.3z"/>
<path d="M201.2 176.1h.6z"/>
<path d="M201.9 176.1h.1z"/>
<path d="M204.5 176.1h.7z"/>
<path d="M205.3 176.1h.4z"/>
<path d="M207.9 176.1h.6z"/>
<path d="M208.6 176.1h.2z"/>
<path d="M211.6 176.1h.6z"/>
<path d="M213 176.1h.6z"/>
<path d="M215 176.1h.2z"/>
<path d="M196.6 176l.2 .1z"/>
<path d="M201.2 176l.5 .1z"/>
<path d="M201.8 176l.2 .1z"/>
<path d="M204.5 176l.7 .1z"/>
<path d="M205.3 176l.3 .1z"/>
<path d="M207.9 176l.9 .1z"/>
<path d="M211.6 176l.7 .1z"/>
<path d="M213 176l.6 .1z"/>
<path d="M215 176l.2 .1z"/>
<path d="M196.6 176h.2z"/>
<path d="M201.1 176h.5z"/>
<path d="M201.7 176h.3z"/>
<path d="M204.5 176h1z"/>
<path d="M207.9 176h.6z"/>
<path d="M208.6 176h.1z"/>
<path d="M211.7 176h.6z"/>
<path d="M213 176h.6z"/>
<path d="M215.5 176h.1z"/>
<path d="M196.6 175.9l.2 .1z"/>
<path d="M201.1 175.9l.5 .1z"/>
<path d="M201.6 175.9l.4 .1z"/>
<path d="M204.5 175.9l.5 .1z"/>
<path d="M205.1 175.9l.4 .1z"/>
<path d="M207.9 175.9l.6 .1z"/>
<path d="M208.6 175.9l.1 .1z"/>
<path d="M211.7 175.9l.6 .1z"/>
<path d="M213 175.9l.6 .1z"/>
<path d="M215 175.9l.1 .1z"/>
<path d="M215.5 175.9l.1 .1z"/>
<path d="M196.7 175.9h.2z"/>
<path d="M201.1 175.9h.4z"/>
<path d="M201.5 175.9h.5z"/>
<path d="M204.4 175.9h.6z"/>
<path d="M205 175.9h.4z"/>
<path d="M207.9 175.9h.8z"/>
<path d="M211.7 175.9h.6z"/>
<path d="M212.9 175.9h.7z"/>
<path d="M215.5 175.9h.1z"/>
<path d="M196.7 175.8l.3 .1z"/>
<path d="M201.1 175.8l.3 .1z"/>
<path d="M201.5 175.8l.5 .1z"/>
<path d="M204.4 175.8l.5 .1z"/>
<path d="M204.9 175.8l.4 .1z"/>
<path d="M207.9 175.8l.6 .1z"/>
<path d="M211.7 175.8l.6 .1z"/>
<path d="M212.8 175.8l.8 .1z"/>
<path d="M215.5 175.8l.1 .1z"/>
<path d="M196.8 175.8h.2z"/>
<path d="M201.1 175.8h.3z"/>
<path d="M201.4 175.8h.6z"/>
<path d="M204.4 175.8h.3z"/>
<path d="M204.8 175.8h.4z"/>
<path d="M207.9 175.8h.6z"/>
<path d="M211.7 175.8h.6z"/>
<path d="M212.8 175.8h.8z"/>
<path d="M215 175.8h.2z"/>
<path d="M215.4 175.8h.2z"/>
<path d="M196.8 175.7l.2 .1z"/>
<path d="M201.1 175.7l.2 .1z"/>
<path d="M201.4 175.7l.4 .1z"/>
<path d="M204.4 175.7l.3 .1z"/>
<path d="M204.8 175.7l.3 .1z"/>
<path d="M207.9 175.7l.7 .1z"/>
<path d="M211.7 175.7l.6 .1z"/>
<path d="M212.7 175.7l.8 .1z"/>
<path d="M215.1 175.7l.1 .1z"/>
<path d="M196.9 175.7h.2z"/>
<path d="M201 175.7h.7z"/>
<path d="M204.3 175.7h.4z"/>
<path d="M204.7 175.7h.4z"/>
<path d="M207.9 175.7h.7z"/>
<path d="M211.7 175.7h.6z"/>
<path d="M212.7 175.7h.7z"/>
<path d="M196.9 175.6l.3 .1z"/>
<path d="M201 175.6l.7 .1z"/>
<path d="M204.3 175.6l.3 .1z"/>
<path d="M204.7 175.6l.3 .1z"/>
<path d="M207.9 175.6l.5 .1z"/>
<path d="M211.7 175.6l.6 .1z"/>
<path d="M212.7 175.6l.7 .1z"/>
<path d="M197 175.6h.3z"/>
<path d="M201 175.6h.2z"/>
<path d="M201.3 175.6h.3z"/>
<path d="M204.3 175.6h.3z"/>
<path d="M204.6 175.6h.3z"/>
<path d="M207.9 175.6h.6z"/>
<path d="M211.7 175.6h.6z"/>
<path d="M212.6 175.6h.8z"/>
<path d="M215.2 175.6h.2z"/>
<path d="M197.1 175.5l.2 .1z"/>
<path d="M201 175.5l.2 .1z"/>
<path d="M201.2 175.5l.3 .1z"/>
<path d="M204.3 175.5l.5 .1z"/>
<path d="M207.9 175.5l.6 .1z"/>
<path d="M211.7 175.5l.6 .1z"/>
<path d="M212.6 175.5l.8 .1z"/>
<path d="M215.2 175.5l.3 .1z"/>
<path d="M197.1 175.5h.3z"/>
<path d="M200.9 175.5h.2z"/>
<path d="M201.2 175.5h.3z"/>
<path d="M202.3 175.5h.2z"/>
<path d="M204.2 175.5h.5z"/>
<path d="M207.9 175.5h.5z"/>
<path d="M211.7 175.5h.6z"/>
<path d="M212.4 175.5h1z"/>
<path d="M215.1 175.5h.5z"/>
<path d="M197.2 175.4l.2 .1z"/>
<path d="M200.9 175.4l.6 .1z"/>
<path d="M204.2 175.4l.5 .1z"/>
<path d="M207.9 175.4l.5 .1z"/>
<path d="M211.7 175.4l.7 .1z"/>
<path d="M212.4 175.4l1 .1z"/>
<path d="M215.1 175.4l.6 .1z"/>
<path d="M197.3 175.4h.2z"/>
<path d="M200.9 175.4h.2z"/>
<path d="M201.1 175.4h.3z"/>
<path d="M201.9 175.4h.2z"/>
<path d="M204.2 175.4h.4z"/>
<path d="M206 175.4h.1z"/>
<path d="M208 175.4h.4z"/>
<path d="M211.7 175.4h1.6z"/>
<path d="M215.1 175.4h.7z"/>
<path d="M197.4 175.3l.2 .1z"/>
<path d="M199 175.3l.3 .1z"/>
<path d="M200.9 175.3l.1 .1z"/>
<path d="M201.1 175.3l.3 .1z"/>
<path d="M201.9 175.3l.2 .1z"/>
<path d="M204.1 175.3l.4 .1z"/>
<path d="M208 175.3l.3 .1z"/>
<path d="M211.7 175.3l1.6 .1z"/>
<path d="M213.3 175.3l.2 .1z"/>
<path d="M215.1 175.3l.2 .1z"/>
<path d="M197.4 175.3h.3z"/>
<path d="M198.9 175.3h.4z"/>
<path d="M200.9 175.3h.5z"/>
<path d="M201.9 175.3h.2z"/>
<path d="M204.1 175.3h.3z"/>
<path d="M208 175.3h.3z"/>
<path d="M211.7 175.3h1.6z"/>
<path d="M215 175.3h.3z"/>
<path d="M197.5 175.2l.3 .1z"/>
<path d="M198.9 175.2l.1 .1z"/>
<path d="M199.2 175.2l.2 .1z"/>
<path d="M200.8 175.2l.5 .1z"/>
<path d="M201.9 175.2l.2 .1z"/>
<path d="M204.1 175.2l.3 .1z"/>
<path d="M208 175.2l.4 .1z"/>
<path d="M211.7 175.2l1.5 .1z"/>
<path d="M215 175.2l.3 .1z"/>
<path d="M197.6 175.2h.3z"/>
<path d="M200.8 175.2h.5z"/>
<path d="M201.9 175.2h.2z"/>
<path d="M204 175.2h.3z"/>
<path d="M207.9 175.2h.5z"/>
<path d="M211.7 175.2h1.5z"/>
<path d="M215 175.2h.3z"/>
<path d="M197.7 175.1l.3 .1z"/>
<path d="M200.8 175.1l.5 .1z"/>
<path d="M201.9 175.1l.2 .1z"/>
<path d="M204 175.1l.3 .1z"/>
<path d="M207.9 175.1l.5 .1z"/>
<path d="M211.7 175.1l1.4 .1z"/>
<path d="M215 175.1l.3 .1z"/>
<path d="M197.8 175.1h.3z"/>
<path d="M200.7 175.1h.5z"/>
<path d="M201.9 175.1h.2z"/>
<path d="M204 175.1h.3z"/>
<path d="M206.1 175.1h.1z"/>
<path d="M207.9 175.1h.3z"/>
<path d="M211.7 175.1h1.4z"/>
<path d="M215 175.1h.3z"/>
<path d="M197.9 175h.3z"/>
<path d="M200.7 175h.5z"/>
<path d="M201.9 175h.2z"/>
<path d="M204 175h.3z"/>
<path d="M206.1 175h.2z"/>
<path d="M207.9 175h.3z"/>
<path d="M211.7 175h1.4z"/>
<path d="M215 175h.3z"/>
<path d="M198 175h.3z"/>
<path d="M200.8 175h.3z"/>
<path d="M201.9 175h.1z"/>
<path d="M207.8 175h.3z"/>
<path d="M198.1 174.9h.2z"/>
<path d="M200.8 174.9h.3z"/>
<path d="M201.9 174.9h.1z"/>
<path d="M204 174.9h.3z"/>
<path d="M206.3 174.9h.2z"/>
<path d="M207.8 174.9h.3z"/>
<path d="M211.7 174.9h1.3z"/>
<path d="M215 174.9h.3z"/>
<path d="M198.2 174.9h.2z"/>
<path d="M205.1 174.9h.1z"/>
<path d="M206.4 174.9h.1z"/>
<path d="M198.2 174.8l.2 .1z"/>
<path d="M200.7 174.8l.3 .1z"/>
<path d="M201.9 174.8l.1 .1z"/>
<path d="M204.1 174.8l.2 .1z"/>
<path d="M206.3 174.8l.2 .1z"/>
<path d="M207.8 174.8l.3 .1z"/>
<path d="M211.7 174.8l1.3 .1z"/>
<path d="M215 174.8l.3 .1z"/>
<path d="M198.2 174.8h.2z"/>
<path d="M200.7 174.8h.3z"/>
<path d="M201.8 174.8h.2z"/>
<path d="M204.1 174.8h.2z"/>
<path d="M206.1 174.8h.1z"/>
<path d="M206.3 174.8h.1z"/>
<path d="M207.8 174.8h.3z"/>
<path d="M211.7 174.8h1.2z"/>
<path d="M215 174.8h.3z"/>
<path d="M198.3 174.7l.2 .1z"/>
<path d="M199 174.7l.3 .1z"/>
<path d="M200.7 174.7l.3 .1z"/>
<path d="M201.8 174.7l.2 .1z"/>
<path d="M204.1 174.7l.2 .1z"/>
<path d="M206 174.7l.3 .1z"/>
<path d="M207.8 174.7l.3 .1z"/>
<path d="M211.7 174.7l1.2 .1z"/>
<path d="M215 174.7l.3 .1z"/>
<path d="M198.4 174.6l.1 .1z"/>
<path d="M200.7 174.6l.3 .1z"/>
<path d="M201.8 174.6l.2 .1z"/>
<path d="M204.1 174.6l.2 .1z"/>
<path d="M205.7 174.6l.5 .1z"/>
<path d="M207.8 174.6l.3 .1z"/>
<path d="M211.7 174.6l1.2 .1z"/>
<path d="M215 174.6l.3 .1z"/>
<path d="M198.4 174.6h.2z"/>
<path d="M200.8 174.6h.3z"/>
<path d="M201.8 174.6h.2z"/>
<path d="M204.1 174.6h.2z"/>
<path d="M205.4 174.6h.7z"/>
<path d="M207.8 174.6h.3z"/>
<path d="M211.7 174.6h1.2z"/>
<path d="M215 174.6h.3z"/>
<path d="M204 174.6h.3z"/>
<path d="M205.2 174.6h.7z"/>
<path d="M207.8 174.6h.2z"/>
<path d="M211.7 174.6h1.1z"/>
<path d="M198.5 174.5h.2z"/>
<path d="M200.9 174.5h.2z"/>
<path d="M201.8 174.5h.2z"/>
<path d="M204 174.5h.4z"/>
<path d="M205.2 174.5h.4z"/>
<path d="M207.8 174.5h.2z"/>
<path d="M211.7 174.5h1.1z"/>
<path d="M215 174.5h.3z"/>
<path d="M204 174.5h.2z"/>
<path d="M204.3 174.5h.2z"/>
<path d="M205.1 174.5h.3z"/>
<path d="M208.7 174.5h.1z"/>
<path d="M211.7 174.5h.3z"/>
<path d="M212.3 174.5h.5z"/>
<path d="M200.9 174.4h.2z"/>
<path d="M201.8 174.4h.2z"/>
<path d="M203.9 174.4h.3z"/>
<path d="M204.3 174.4h.2z"/>
<path d="M205 174.4h.3z"/>
<path d="M207.8 174.4h.2z"/>
<path d="M211.7 174.4h.3z"/>
<path d="M212.3 174.4h.4z"/>
<path d="M215 174.4h.3z"/>
<path d="M200.9 174.3l.2 .1z"/>
<path d="M201.8 174.3l.2 .1z"/>
<path d="M203.9 174.3l.2 .1z"/>
<path d="M204.3 174.3l.2 .1z"/>
<path d="M204.9 174.3l.3 .1z"/>
<path d="M207.8 174.3l.2 .1z"/>
<path d="M211.7 174.3l.3 .1z"/>
<path d="M212.3 174.3l.4 .1z"/>
<path d="M215 174.3l.3 .1z"/>
<path d="M201 174.3h.2z"/>
<path d="M201.8 174.3h.2z"/>
<path d="M202.3 174.3h.2z"/>
<path d="M203.9 174.3h.2z"/>
<path d="M204.3 174.3h.2z"/>
<path d="M204.8 174.3h.3z"/>
<path d="M207.7 174.3h.2z"/>
<path d="M211.7 174.3h.3z"/>
<path d="M212.3 174.3h.4z"/>
<path d="M215 174.3h.3z"/>
<path d="M201 174.2l.2 .1z"/>
<path d="M201.8 174.2l.2 .1z"/>
<path d="M203.9 174.2l.2 .1z"/>
<path d="M204.3 174.2l.2 .1z"/>
<path d="M204.8 174.2l.3 .1z"/>
<path d="M207.7 174.2l.2 .1z"/>
<path d="M211.7 174.2l.2 .1z"/>
<path d="M212.3 174.2l.4 .1z"/>
<path d="M215 174.2l.3 .1z"/>
<path d="M201 174.2h.2z"/>
<path d="M201.8 174.2h.2z"/>
<path d="M203.9 174.2h.2z"/>
<path d="M204.3 174.2h.2z"/>
<path d="M204.8 174.2h.2z"/>
<path d="M207.6 174.2h.3z"/>
<path d="M211.7 174.2h.2z"/>
<path d="M212.3 174.2h.3z"/>
<path d="M215 174.2h.3z"/>
<path d="M201 174.1l.2 .1z"/>
<path d="M201.9 174.1l.2 .1z"/>
<path d="M203.9 174.1l.2 .1z"/>
<path d="M204.3 174.1l.2 .1z"/>
<path d="M204.8 174.1l.2 .1z"/>
<path d="M207.6 174.1l.2 .1z"/>
<path d="M211.7 174.1l.2 .1z"/>
<path d="M212.2 174.1l.4 .1z"/>
<path d="M215 174.1l.3 .1z"/>
<path d="M201 174.1h.2z"/>
<path d="M201.9 174.1h.2z"/>
<path d="M203.9 174.1h.2z"/>
<path d="M204.3 174.1h.2z"/>
<path d="M204.7 174.1h.2z"/>
<path d="M207.6 174.1h.2z"/>
<path d="M211.7 174.1h.2z"/>
<path d="M215.1 174.1h.2z"/>
<path d="M201.1 174.1h.2z"/>
<path d="M212.2 174.1h.1z"/>
<path d="M201.1 174h.2z"/>
<path d="M202 174h.1z"/>
<path d="M203.8 174h.2z"/>
<path d="M204.3 174h.2z"/>
<path d="M204.7 174h.2z"/>
<path d="M207.6 174h.2z"/>
<path d="M210.7 174h.1z"/>
<path d="M211.7 174h.2z"/>
<path d="M212.2 174h.4z"/>
<path d="M215.1 174h.5z"/>
<path d="M201.1 173.9l.2 .1z"/>
<path d="M202 173.9l.2 .1z"/>
<path d="M203.8 173.9l.2 .1z"/>
<path d="M204.3 173.9l.2 .1z"/>
<path d="M204.7 173.9l.2 .1z"/>
<path d="M207.6 173.9l.2 .1z"/>
<path d="M210.6 173.9l.2 .1z"/>
<path d="M211.7 173.9l.3 .1z"/>
<path d="M212.2 173.9l.4 .1z"/>
<path d="M215.2 173.9l.4 .1z"/>
<path d="M215.9 173.9l.2 .1z"/>
<path d="M201.1 173.9h.2z"/>
<path d="M202 173.9h.2z"/>
<path d="M203.8 173.9h.2z"/>
<path d="M204.3 173.9h.2z"/>
<path d="M204.7 173.9h.2z"/>
<path d="M207.6 173.9h.2z"/>
<path d="M210.5 173.9h.2z"/>
<path d="M211.7 173.9h.3z"/>
<path d="M215.2 173.9h.2z"/>
<path d="M201.1 173.8l.2 .1z"/>
<path d="M202.1 173.8l.1 .1z"/>
<path d="M203.8 173.8l.2 .1z"/>
<path d="M204.3 173.8l.2 .1z"/>
<path d="M204.7 173.8l.2 .1z"/>
<path d="M207.5 173.8l.2 .1z"/>
<path d="M210.5 173.8l.3 .1z"/>
<path d="M211.7 173.8l.3 .1z"/>
<path d="M215.2 173.8l.1 .1z"/>
<path d="M215.7 173.8l.2 .1z"/>
<path d="M201.2 173.8h.2z"/>
<path d="M202.1 173.8h.1z"/>
<path d="M203.8 173.8h.2z"/>
<path d="M204.3 173.8h.2z"/>
<path d="M204.7 173.8h.2z"/>
<path d="M207.5 173.8h.2z"/>
<path d="M210.4 173.8h.3z"/>
<path d="M211.7 173.8h.3z"/>
<path d="M215.1 173.8h.2z"/>
<path d="M215.7 173.8h.2z"/>
<path d="M201.2 173.7l.2 .1z"/>
<path d="M202.1 173.7l.2 .1z"/>
<path d="M203.8 173.7l.2 .1z"/>
<path d="M204.3 173.7l.2 .1z"/>
<path d="M204.7 173.7l.2 .1z"/>
<path d="M207.5 173.7l.2 .1z"/>
<path d="M210.3 173.7l.2 .1z"/>
<path d="M211.7 173.7l.2 .1z"/>
<path d="M212.2 173.7l.2 .1z"/>
<path d="M215 173.7l.3 .1z"/>
<path d="M201.2 173.7h.2z"/>
<path d="M202.1 173.7h.2z"/>
<path d="M203.8 173.7h.2z"/>
<path d="M204.3 173.7h.2z"/>
<path d="M204.7 173.7h.2z"/>
<path d="M205.2 173.7h.2z"/>
<path d="M207.5 173.7h.2z"/>
<path d="M210.3 173.7h.2z"/>
<path d="M211.7 173.7h.2z"/>
<path d="M215 173.7h.3z"/>
<path d="M201.3 173.6l.1 .1z"/>
<path d="M202.2 173.6l.1 .1z"/>
<path d="M203.8 173.6l.2 .1z"/>
<path d="M204.3 173.6l.2 .1z"/>
<path d="M204.7 173.6l.2 .1z"/>
<path d="M207.5 173.6l.2 .1z"/>
<path d="M210.2 173.6l.3 .1z"/>
<path d="M211.7 173.6l.2 .1z"/>
<path d="M215.1 173.6l.2 .1z"/>
<path d="M201.3 173.6h.2z"/>
<path d="M202.2 173.6h.1z"/>
<path d="M203.9 173.6h.2z"/>
<path d="M204.3 173.6h.2z"/>
<path d="M204.7 173.6h.2z"/>
<path d="M207.5 173.6h.2z"/>
<path d="M210.2 173.6h.2z"/>
<path d="M211.7 173.6h.2z"/>
<path d="M212.2 173.6h.3z"/>
<path d="M215.2 173.6h.2z"/>
<path d="M201.3 173.5l.2 .1z"/>
<path d="M202.2 173.5l.2 .1z"/>
<path d="M203.9 173.5l.3 .1z"/>
<path d="M204.3 173.5l.2 .1z"/>
<path d="M204.7 173.5l.2 .1z"/>
<path d="M207.5 173.5l.2 .1z"/>
<path d="M210.1 173.5l.1 .1z"/>
<path d="M211.7 173.5l.2 .1z"/>
<path d="M212.1 173.5l.5 .1z"/>
<path d="M215.1 173.5l.1 .1z"/>
<path d="M201.3 173.5h.2z"/>
<path d="M204 173.5h.2z"/>
<path d="M204.3 173.5h.3z"/>
<path d="M204.7 173.5h.2z"/>
<path d="M207.6 173.5h.2z"/>
<path d="M210 173.5h.2z"/>
<path d="M211.7 173.5h.1z"/>
<path d="M212.1 173.5h.5z"/>
<path d="M215.1 173.5h.2z"/>
<path d="M201.4 173.4l.1 .1z"/>
<path d="M202.3 173.4l.1 .1z"/>
<path d="M204 173.4l.3 .1z"/>
<path d="M204.4 173.4l.2 .1z"/>
<path d="M204.7 173.4l.2 .1z"/>
<path d="M207.6 173.4l.2 .1z"/>
<path d="M210 173.4l.2 .1z"/>
<path d="M211.7 173.4l.1 .1z"/>
<path d="M212.1 173.4l.4 .1z"/>
<path d="M215.2 173.4l.1 .1z"/>
<path d="M201.4 173.4h.1z"/>
<path d="M204.2 173.4h.1z"/>
<path d="M204.4 173.4h.2z"/>
<path d="M204.7 173.4h.2z"/>
<path d="M207.6 173.4h.2z"/>
<path d="M208.8 173.4h.2z"/>
<path d="M209.9 173.4h.2z"/>
<path d="M211.6 173.4h.2z"/>
<path d="M212.1 173.4h.3z"/>
<path d="M215.2 173.4h.2z"/>
<path d="M201.4 173.3l.2 .1z"/>
<path d="M202.3 173.3l.2 .1z"/>
<path d="M204.2 173.3l.2 .1z"/>
<path d="M204.4 173.3l.2 .1z"/>
<path d="M204.7 173.3l.2 .1z"/>
<path d="M207.6 173.3l.2 .1z"/>
<path d="M208.8 173.3l.3 .1z"/>
<path d="M209.8 173.3l.2 .1z"/>
<path d="M211.6 173.3l.2 .1z"/>
<path d="M212.1 173.3l.3 .1z"/>
<path d="M215.3 173.3l.2 .1z"/>
<path d="M204.3 173.3h.3z"/>
<path d="M204.7 173.3h.2z"/>
<path d="M207.6 173.3h.2z"/>
<path d="M208.8 173.3h.3z"/>
<path d="M209.8 173.3h.2z"/>
<path d="M211.6 173.3h.2z"/>
<path d="M212.1 173.3h.2z"/>
<path d="M212.6 173.3h.1z"/>
<path d="M201.4 173.2l.2 .1z"/>
<path d="M204.3 173.2l.3 .1z"/>
<path d="M204.7 173.2l.2 .1z"/>
<path d="M207.6 173.2l.2 .1z"/>
<path d="M209 173.2l.2 .1z"/>
<path d="M209.7 173.2l.3 .1z"/>
<path d="M211.6 173.2l.1 .1z"/>
<path d="M212.1 173.2l.2 .1z"/>
<path d="M212.6 173.2l.1 .1z"/>
<path d="M216.2 173.2l.2 .1z"/>
<path d="M201.5 173.2h.2z"/>
<path d="M204.4 173.2h.5z"/>
<path d="M207.6 173.2h.2z"/>
<path d="M209.1 173.2h.2z"/>
<path d="M209.7 173.2h.2z"/>
<path d="M211.6 173.2h.1z"/>
<path d="M212.1 173.2h.3z"/>
<path d="M212.5 173.2h.2z"/>
<path d="M215.4 173.2h.3z"/>
<path d="M216.2 173.2h.3z"/>
<path d="M201.5 173.1l.2 .1z"/>
<path d="M203.2 173.1l.4 .1z"/>
<path d="M204.4 173.1l.5 .1z"/>
<path d="M207.6 173.1l.2 .1z"/>
<path d="M209.2 173.1l.2 .1z"/>
<path d="M209.6 173.1l.1 .1z"/>
<path d="M211.6 173.1l.1 .1z"/>
<path d="M212 173.1l.3 .1z"/>
<path d="M212.5 173.1l.2 .1z"/>
<path d="M215.4 173.1l.4 .1z"/>
<path d="M201.6 173.1h.2z"/>
<path d="M203 173.1h.6z"/>
<path d="M204.4 173.1h.5z"/>
<path d="M207.6 173.1h.2z"/>
<path d="M208.7 173.1h.2z"/>
<path d="M209.3 173.1h.5z"/>
<path d="M211.5 173.1h.2z"/>
<path d="M212 173.1h.3z"/>
<path d="M212.5 173.1h.2z"/>
<path d="M215.5 173.1h.4z"/>
<path d="M201.7 173l.2 .1z"/>
<path d="M202.5 173l.1 .1z"/>
<path d="M203.1 173l.4 .1z"/>
<path d="M204.5 173l.5 .1z"/>
<path d="M205.4 173l.1 .1z"/>
<path d="M207.6 173l.2 .1z"/>
<path d="M208.8 173l.1 .1z"/>
<path d="M209.4 173l.3 .1z"/>
<path d="M211.5 173l.2 .1z"/>
<path d="M212 173l.4 .1z"/>
<path d="M212.5 173l.2 .1z"/>
<path d="M215.5 173l.4 .1z"/>
<path d="M216.1 173l.2 .1z"/>
<path d="M201.7 173h.2z"/>
<path d="M203.1 173h.4z"/>
<path d="M204.5 173h.5z"/>
<path d="M207.6 173h.2z"/>
<path d="M209.4 173h.3z"/>
<path d="M211.5 173h.1z"/>
<path d="M212 173h.4z"/>
<path d="M212.5 173h.2z"/>
<path d="M215.4 173h.2z"/>
<path d="M216 173h.2z"/>
<path d="M201.8 172.9l.2 .1z"/>
<path d="M203.1 172.9l.3 .1z"/>
<path d="M204.5 172.9l.5 .1z"/>
<path d="M207.6 172.9l.2 .1z"/>
<path d="M208.8 172.9l.2 .1z"/>
<path d="M209.3 172.9l.2 .1z"/>
<path d="M211.5 172.9l.1 .1z"/>
<path d="M212 172.9l.4 .1z"/>
<path d="M212.5 172.9l.2 .1z"/>
<path d="M215.4 172.9l.2 .1z"/>
<path d="M201.9 172.9h.2z"/>
<path d="M203 172.9h.3z"/>
<path d="M204.6 172.9h.4z"/>
<path d="M207.6 172.9h.3z"/>
<path d="M211.5 172.9h.2z"/>
<path d="M212 172.9h.3z"/>
<path d="M212.5 172.9h.2z"/>
<path d="M215.4 172.9h.2z"/>
<path d="M201.9 172.8l.3 .1z"/>
<path d="M203 172.8l.3 .1z"/>
<path d="M204.6 172.8l.3 .1z"/>
<path d="M205.7 172.8l.2 .1z"/>
<path d="M207.6 172.8l.3 .1z"/>
<path d="M209.2 172.8l.2 .1z"/>
<path d="M211.4 172.8l.3 .1z"/>
<path d="M212 172.8l.3 .1z"/>
<path d="M212.5 172.8l.2 .1z"/>
<path d="M215.4 172.8l.2 .1z"/>
<path d="M215.9 172.8l.2 .1z"/>
<path d="M202 172.8h.3z"/>
<path d="M203 172.8h.3z"/>
<path d="M204.7 172.8h.2z"/>
<path d="M205.7 172.8h.3z"/>
<path d="M207.6 172.8h.3z"/>
<path d="M209.2 172.8h.2z"/>
<path d="M211.4 172.8h.2z"/>
<path d="M212 172.8h.3z"/>
<path d="M212.5 172.8h.2z"/>
<path d="M215.9 172.8h.4z"/>
<path d="M202.1 172.7l.2 .1z"/>
<path d="M203 172.7l.3 .1z"/>
<path d="M204.7 172.7l.2 .1z"/>
<path d="M205.7 172.7l.4 .1z"/>
<path d="M207.7 172.7l.2 .1z"/>
<path d="M209.1 172.7l.2 .1z"/>
<path d="M211.4 172.7l.3 .1z"/>
<path d="M212 172.7l.2 .1z"/>
<path d="M212.5 172.7l.2 .1z"/>
<path d="M215.5 172.7l.2 .1z"/>
<path d="M215.8 172.7l.2 .1z"/>
<path d="M202.2 172.7h.2z"/>
<path d="M202.9 172.7h.4z"/>
<path d="M204.8 172.7h.2z"/>
<path d="M205.3 172.7h.1z"/>
<path d="M205.7 172.7h.4z"/>
<path d="M207.8 172.7h.2z"/>
<path d="M209 172.7h.3z"/>
<path d="M211.4 172.7h.2z"/>
<path d="M211.9 172.7h.3z"/>
<path d="M212.5 172.7h.2z"/>
<path d="M216.2 172.7h.3z"/>
<path d="M217.4 172.7h.2z"/>
<path d="M202.3 172.6l.2 .1z"/>
<path d="M202.8 172.6l.5 .1z"/>
<path d="M204.8 172.6l.2 .1z"/>
<path d="M205.2 172.6l.2 .1z"/>
<path d="M205.6 172.6l.4 .1z"/>
<path d="M207.8 172.6l.2 .1z"/>
<path d="M209 172.6l.2 .1z"/>
<path d="M211.4 172.6l.3 .1z"/>
<path d="M211.9 172.6l.3 .1z"/>
<path d="M212.5 172.6l.2 .1z"/>
<path d="M215.8 172.6l.2 .1z"/>
<path d="M217.6 172.6l.1 .1z"/>
<path d="M202.3 172.6h.8z"/>
<path d="M203.1 172.6h.2z"/>
<path d="M204.9 172.6h.5z"/>
<path d="M205.6 172.6h.3z"/>
<path d="M207.8 172.6h.2z"/>
<path d="M208.9 172.6h.2z"/>
<path d="M211.4 172.6h.2z"/>
<path d="M212 172.6h.2z"/>
<path d="M212.5 172.6h.2z"/>
<path d="M215 172.6h.3z"/>
<path d="M215.5 172.6h.1z"/>
<path d="M217.3 172.6h.2z"/>
<path d="M202.4 172.5l.6 .1z"/>
<path d="M204.9 172.5l.5 .1z"/>
<path d="M205.6 172.5l.3 .1z"/>
<path d="M207.8 172.5l.2 .1z"/>
<path d="M208.9 172.5l.2 .1z"/>
<path d="M211.5 172.5l.1 .1z"/>
<path d="M212 172.5l.1 .1z"/>
<path d="M212.5 172.5l.2 .1z"/>
<path d="M214.9 172.5l.4 .1z"/>
<path d="M215.5 172.5l.1 .1z"/>
<path d="M202.5 172.5h.5z"/>
<path d="M203.4 172.5h.2z"/>
<path d="M205 172.5h.5z"/>
<path d="M205.6 172.5h.3z"/>
<path d="M208.7 172.5h.3z"/>
<path d="M211.5 172.5h.2z"/>
<path d="M212 172.5h.1z"/>
<path d="M212.5 172.5h.2z"/>
<path d="M214.9 172.5h.4z"/>
<path d="M215.5 172.5h.1z"/>
<path d="M215.8 172.5h.1z"/>
<path d="M217.7 172.5h.1z"/>
<path d="M202.6 172.4l.4 .1z"/>
<path d="M203.2 172.4l.1 .1z"/>
<path d="M203.4 172.4l.2 .1z"/>
<path d="M205 172.4l.5 .1z"/>
<path d="M205.6 172.4l.2 .1z"/>
<path d="M207.9 172.4l.1 .1z"/>
<path d="M208.7 172.4l.2 .1z"/>
<path d="M211.5 172.4l.2 .1z"/>
<path d="M212.5 172.4l.2 .1z"/>
<path d="M214.8 172.4l.6 .1z"/>
<path d="M215.5 172.4l.1 .1z"/>
<path d="M217.1 172.4l.3 .1z"/>
<path d="M202.6 172.4h.5z"/>
<path d="M203.1 172.4h.3z"/>
<path d="M205 172.4h.6z"/>
<path d="M208.7 172.4h.2z"/>
<path d="M211.5 172.4h.2z"/>
<path d="M212.5 172.4h.2z"/>
<path d="M214.8 172.4h.2z"/>
<path d="M215.2 172.4h.2z"/>
<path d="M215.7 172.4h.2z"/>
<path d="M217.2 172.4h.3z"/>
<path d="M202.6 172.3l1 .1z"/>
<path d="M205 172.3l.5 .1z"/>
<path d="M207.9 172.3l.2 .1z"/>
<path d="M208.7 172.3l.1 .1z"/>
<path d="M211.5 172.3l.3 .1z"/>
<path d="M212.5 172.3l.2 .1z"/>
<path d="M214.8 172.3l.1 .1z"/>
<path d="M215.2 172.3l.4 .1z"/>
<path d="M216.1 172.3l.3 .1z"/>
<path d="M217.3 172.3l.2 .1z"/>
<path d="M202.7 172.3h.8z"/>
<path d="M205 172.3h.5z"/>
<path d="M211.6 172.3h.2z"/>
<path d="M212.5 172.3h.3z"/>
<path d="M214.8 172.3h.1z"/>
<path d="M215.2 172.3h.4z"/>
<path d="M216.6 172.3h.2z"/>
<path d="M216.9 172.3h.2z"/>
<path d="M202.7 172.2l.8 .1z"/>
<path d="M205 172.2l.5 .1z"/>
<path d="M205.6 172.2l.2 .1z"/>
<path d="M205.9 172.2l.2 .1z"/>
<path d="M208.6 172.2l.2 .1z"/>
<path d="M211.6 172.2l.2 .1z"/>
<path d="M212.5 172.2l.2 .1z"/>
<path d="M214.7 172.2l.2 .1z"/>
<path d="M215.2 172.2l.2 .1z"/>
<path d="M216.5 172.2l.2 .1z"/>
<path d="M216.8 172.2l.3 .1z"/>
<path d="M217.5 172.2l.2 .1z"/>
<path d="M202.7 172.2h.8z"/>
<path d="M205 172.2h.8z"/>
<path d="M205.9 172.2h.2z"/>
<path d="M208.6 172.2h.2z"/>
<path d="M211.6 172.2h.2z"/>
<path d="M212.5 172.2h.2z"/>
<path d="M214.7 172.2h.2z"/>
<path d="M215.2 172.2h.1z"/>
<path d="M216.8 172.2h.4z"/>
<path d="M217.6 172.2h.2z"/>
<path d="M202.8 172.1h.6z"/>
<path d="M205 172.1h.9z"/>
<path d="M208 172.1h.3z"/>
<path d="M208.6 172.1h.5z"/>
<path d="M211.6 172.1h.3z"/>
<path d="M212.5 172.1h.2z"/>
<path d="M214.7 172.1h.2z"/>
<path d="M215.2 172.1h.1z"/>
<path d="M215.6 172.1h.2z"/>
<path d="M217.1 172.1h.2z"/>
<path d="M217.7 172.1h.2z"/>
<path d="M202.9 172.1h.4z"/>
<path d="M205 172.1h1z"/>
<path d="M208 172.1h.4z"/>
<path d="M217.2 172.1h.2z"/>
<path d="M217.8 172.1h.2z"/>
<path d="M205.1 172l.9 .1z"/>
<path d="M208 172l.4 .1z"/>
<path d="M208.6 172l.5 .1z"/>
<path d="M211.6 172l.3 .1z"/>
<path d="M212.5 172l.2 .1z"/>
<path d="M214.7 172l.2 .1z"/>
<path d="M215.2 172l.1 .1z"/>
<path d="M215.6 172l.2 .1z"/>
<path d="M217.3 172l.2 .1z"/>
<path d="M217.6 172l.2 .1z"/>
<path d="M217.9 172l.2 .1z"/>
<path d="M205.1 172h.8z"/>
<path d="M208 172h.5z"/>
<path d="M208.5 172h.6z"/>
<path d="M211.7 172h.2z"/>
<path d="M212.5 172h.2z"/>
<path d="M214.7 172h.2z"/>
<path d="M215.2 172h.1z"/>
<path d="M217.4 172h.2z"/>
<path d="M217.7 172h.2z"/>
<path d="M218 172h.2z"/>
<path d="M205.2 171.9l.7 .1z"/>
<path d="M208 171.9l.5 .1z"/>
<path d="M208.5 171.9l.6 .1z"/>
<path d="M211.7 171.9l.2 .1z"/>
<path d="M212.5 171.9l.2 .1z"/>
<path d="M214.7 171.9l.2 .1z"/>
<path d="M215.5 171.9l.2 .1z"/>
<path d="M217.5 171.9l.2 .1z"/>
<path d="M217.8 171.9l.2 .1z"/>
<path d="M218.1 171.9l.2 .1z"/>
<path d="M205.3 171.9h.5z"/>
<path d="M208 171.9h.9z"/>
<path d="M211.7 171.9h.2z"/>
<path d="M212.5 171.9h.2z"/>
<path d="M214.7 171.9h.2z"/>
<path d="M215.5 171.9h.2z"/>
<path d="M217.6 171.9h.2z"/>
<path d="M217.9 171.9h.2z"/>
<path d="M218.2 171.9h.2z"/>
<path d="M207.9 171.8l.8 .1z"/>
<path d="M208.8 171.8l.3 .1z"/>
<path d="M211.7 171.8l.2 .1z"/>
<path d="M212.5 171.8l.2 .1z"/>
<path d="M214.7 171.8l.2 .1z"/>
<path d="M217.7 171.8l.2 .1z"/>
<path d="M218 171.8l.2 .1z"/>
<path d="M218.3 171.8l.2 .1z"/>
<path d="M207.8 171.8h.9z"/>
<path d="M208.8 171.8h.3z"/>
<path d="M211.7 171.8h.2z"/>
<path d="M212.5 171.8h.2z"/>
<path d="M214.7 171.8h.2z"/>
<path d="M215.5 171.8h.1z"/>
<path d="M217.8 171.8h.2z"/>
<path d="M218.1 171.8h.2z"/>
<path d="M218.4 171.8h.2z"/>
<path d="M207.8 171.7h.6z"/>
<path d="M208.5 171.7h.2z"/>
<path d="M211.7 171.7h.3z"/>
<path d="M214.7 171.7h.2z"/>
<path d="M215.7 171.7h.2z"/>
<path d="M218.2 171.7h.2z"/>
<path d="M218.5 171.7h.2z"/>
<path d="M207.7 171.7h.2z"/>
<path d="M208 171.7h.4z"/>
<path d="M215.4 171.7h.2z"/>
<path d="M218.3 171.7h.2z"/>
<path d="M218.6 171.7h.2z"/>
<path d="M207.6 171.6h.3z"/>
<path d="M208 171.6h.4z"/>
<path d="M208.5 171.6h.2z"/>
<path d="M211.8 171.6h.1z"/>
<path d="M214.7 171.6h.2z"/>
<path d="M215.4 171.6h.1z"/>
<path d="M218.4 171.6h.2z"/>
<path d="M207.6 171.6h.2z"/>
<path d="M215.8 171.6h.2z"/>
<path d="M218.2 171.6h.1z"/>
<path d="M218.6 171.6h.1z"/>
<path d="M207.5 171.5l.2 .1z"/>
<path d="M208 171.5l.7 .1z"/>
<path d="M208.8 171.5l.2 .1z"/>
<path d="M212.5 171.5l.1 .1z"/>
<path d="M214.7 171.5l.2 .1z"/>
<path d="M215.3 171.5l.3 .1z"/>
<path d="M215.8 171.5l.2 .1z"/>
<path d="M218.3 171.5l.1 .1z"/>
<path d="M218.7 171.5l.1 .1z"/>
<path d="M207.5 171.4l.2 .1z"/>
<path d="M208 171.4l.7 .1z"/>
<path d="M208.9 171.4l.1 .1z"/>
<path d="M212.5 171.4l.1 .1z"/>
<path d="M214.7 171.4l.2 .1z"/>
<path d="M215.4 171.4l.2 .1z"/>
<path d="M215.8 171.4l.2 .1z"/>
<path d="M218.8 171.4l.1 .1z"/>
<path d="M207.4 171.4h.2z"/>
<path d="M208 171.4h.7z"/>
<path d="M212.3 171.4h.3z"/>
<path d="M214.7 171.4h.2z"/>
<path d="M215.4 171.4h.2z"/>
<path d="M215.8 171.4h.2z"/>
<path d="M218.9 171.4h.2z"/>
<path d="M207.3 171.3l.3 .1z"/>
<path d="M208 171.3l.6 .1z"/>
<path d="M212.1 171.3l.2 .1z"/>
<path d="M212.5 171.3l.1 .1z"/>
<path d="M214.7 171.3l.2 .1z"/>
<path d="M215.4 171.3l.1 .1z"/>
<path d="M215.8 171.3l.1 .1z"/>
<path d="M218.5 171.3l.2 .1z"/>
<path d="M219 171.3l.2 .1z"/>
<path d="M207.2 171.3h.3z"/>
<path d="M208 171.3h.6z"/>
<path d="M215.4 171.3h.2z"/>
<path d="M215.8 171.3h.2z"/>
<path d="M218.6 171.3h.2z"/>
<path d="M219.1 171.3h.2z"/>
<path d="M207.2 171.3h.2z"/>
<path d="M208 171.3h.7z"/>
<path d="M214.8 171.3h.1z"/>
<path d="M215.8 171.3h.1z"/>
<path d="M219.2 171.3h.2z"/>
<path d="M207.1 171.2h.2z"/>
<path d="M208.1 171.2h.8z"/>
<path d="M212 171.2h.2z"/>
<path d="M214.8 171.2h.1z"/>
<path d="M215.5 171.2h.3z"/>
<path d="M219.3 171.2h.2z"/>
<path d="M215.6 171.2h.2z"/>
<path d="M207 171.1h.2z"/>
<path d="M208.2 171.1h.6z"/>
<path d="M212 171.1h.3z"/>
<path d="M215.6 171.1h.2z"/>
<path d="M219.3 171.1h.2z"/>
<path d="M206.9 171l.3 .1z"/>
<path d="M208.3 171l.4 .1z"/>
<path d="M211.8 171l.5 .1z"/>
<path d="M216 171l.2 .1z"/>
<path d="M219.3 171l.2 .1z"/>
<path d="M211.8 171h.5z"/>
<path d="M215.6 171h.2z"/>
<path d="M216 171h.2z"/>
<path d="M206.8 170.9l.3 .1z"/>
<path d="M211.8 170.9l.5 .1z"/>
<path d="M206.7 170.9h.3z"/>
<path d="M211.8 170.9h.5z"/>
<path d="M214.9 170.9h.1z"/>
<path d="M206.7 170.8l.2 .1z"/>
<path d="M211.8 170.8l.5 .1z"/>
<path d="M211.8 170.8h.5z"/>
<path d="M206.6 170.8h.2z"/>
<path d="M211.8 170.8h.4z"/>
<path d="M215.8 170.8h.1z"/>
<path d="M206.5 170.7h.2z"/>
<path d="M211.8 170.7h.4z"/>
<path d="M206.4 170.6l.3 .1z"/>
<path d="M211.8 170.6l.4 .1z"/>
<path d="M215.4 170.6l.2 .1z"/>
<path d="M206.2 170.6h.3z"/>
<path d="M211.8 170.6h.7z"/>
<path d="M206.2 170.5l.3 .1z"/>
<path d="M211.8 170.5l.8 .1z"/>
<path d="M214.7 170.5l.2 .1z"/>
<path d="M215.4 170.5l.2 .1z"/>
<path d="M206.2 170.5h.2z"/>
<path d="M211.8 170.5h.8z"/>
<path d="M214.7 170.5h.2z"/>
<path d="M215.5 170.5h.2z"/>
<path d="M211.8 170.4l.9 .1z"/>
<path d="M214.7 170.4l.2 .1z"/>
<path d="M215.3 170.4l.4 .1z"/>
<path d="M211.8 170.4h.9z"/>
<path d="M214.7 170.4h.1z"/>
<path d="M215.5 170.4h.1z"/>
<path d="M206.1 170.3l.2 .1z"/>
<path d="M211.9 170.3l.8 .1z"/>
<path d="M214.7 170.3l.1 .1z"/>
<path d="M211.9 170.3h.8z"/>
<path d="M215.4 170.3h.2z"/>
<path d="M215.1 170.2l.2 .1z"/>
<path d="M215.4 170.2l.1 .1z"/>
<path d="M215.3 170.2h.2z"/>
<path d="M215.6 170.1h.2z"/>
<path d="M120.3 55.1h.9v.2h-.9z"/>
<path d="M120.7 54.8h.1v.8h-.1z"/>
<path d="M74.8 57.5h4.1v.5h-4.1z"/>
<path d="M74.8 56.5h4.1v.5h-4.1z"/>
<path d="M135.8 117.4h4v.5h-4z"/>
<path d="M135.8 118.4h4v.5h-4z"/>
<path d="M151 117.4h4.1v.5h-4.1z"/>
<path d="M151 118.4h4.1v.5h-4.1z"/>
<path d="M34.2 164.1h4v.5h-4z"/>
<path d="M34.2 163.1h4v.5h-4z"/>
<path d="M201.8 103.2h4v.5h-4z"/>
<path d="M201.8 102.2h4v.5h-4z"/>
</g>
<g fill="none" stroke="#c90d0c" stroke-width=".21">
<path d="M22.2 15.3h252.7v171.4h-252.7zM59.1 15.3v2.8M59.1 19.6v2.9M64.4 11.5v3.8M106.5 11.5v3.8M142.9 15.3v2.8M142.9 19.6v2.9M148.6 11.5v3.8M190.7 11.5v3.8M191.1 15.3v2.8M191.1 19.6v2.9M232.8 11.5v3.8"/>
<path d="M41.2 30.5v.6M41.2 34.6v.6M45.2 34.6v.5M45.3 30.4v.6M59.1 24v2.8M59.1 28.3v2.8M59.1 32.6v2.9M59.1 37v2.8M99.7 28v5.1M142.9 24v2.8M142.9 28.3v2.8M142.9 32.6v2.9"/>
<path d="M142.9 37v2.8M159.3 36.4h1.2M159.9 35.8v1.2M159.9 37.7v5M169.4 36.4h1.3M170.1 35.8v1.2M170.1 37.7v5M191.1 24v2.8M191.1 28.3v2.8M191.1 32.6v2.9M191.1 37v2.8M205.7 36.9h1.3"/>
<path d="M206.4 36.3v1.2M206.4 38.2v7.6M211.4 38.2v7.6M221.6 38.2v7.6M229.2 38.2v7.6M241.9 38.2v7.6M247 38.2v7.6M18.4 58.2h3.8M36.2 45.8v5.1M41.3 45.8h2.5M43.8 44.5v2.6M46.4 53.4v2.5"/>
<path d="M59.1 41.3v2.8M59.1 45.6v2.9M59.1 50v2.8M59.1 54.3v2.8M59.1 58.6v2.9M67.3 40.7h1.3M68 40.1v1.2M69.2 40.7h2.6M76.9 53.4v3.1M76.9 58v3M81.9 40.7h5.1M92.1 57.9v3.1"/>
<path d="M97.2 55.9v5.1M102.2 55.9v5.1M107.3 55.9v5.1M112.4 40.7h5.1M122.6 53.4v2.5M122.6 57v4M130.2 40.7h2.5M133.3 40.7h1.3M134 40.1v1.2M142.9 41.3v2.8M142.9 45.6v2.9M142.9 50v2.8"/>
<path d="M142.9 54.3v2.8M142.9 58.6v2.9M156.5 44.8h.1M156.5 44.7h.4M156.6 44.6h.6M156.6 46h.1M156.6 45.9h.3M156.7 44.4h.6M156.7 44.3h.5M156.7 45.8h.5M156.7 44.2h.4M156.7 45.7h.7"/>
<path d="M156.8 44.1h.1M156.8 45.6h.6M156.8 44l.6 .5-.9 .4zM156.8 45.4h.4M156.9 45.3h.2M157 45.2h.1M157 45.1l.5 .6-.9 .3zM157.9 43.5l-1.4 1.4M158 44.6l-1.4 1.4M159.9 45.3v5.1M159.9 55.4v5.1M166.6 44.8h.2"/>
<path d="M166.7 44.7h.4M166.8 44.6h.5M166.8 46h.1M166.8 45.9h.2M166.8 44.4h.6M166.9 44.3h.4M166.9 45.8h.4M166.9 44.2h.3M166.9 45.7h.7M167 44.1h.1M167 45.6h.5M167 45.4h.4"/>
<path d="M167 44l.5 .5-.9 .4zM167.1 45.3h.2M167.1 45.2h.1M167.1 45.1l.5 .6-.8 .3zM168 43.5l-1.4 1.4M168.1 44.6l-1.3 1.4M170.1 45.3v5.1M170.1 55.4v5.1M191.1 41.3v2.8M191.1 45.6v2.9M191.1 50v2.8M191.1 54.3v2.8"/>
<path d="M191.1 58.6v2.9M206.4 50.9v7.6M208.9 40.7v5.1M208.9 50.9v5M211.4 50.9v5M214 40.7v5.1M214 50.9v5M216.5 40.7v5.1M216.5 50.9v7.6M219.1 40.7v5.1M219.1 50.9v5M221.6 50.9v5"/>
<path d="M224.1 40.7v5.1M224.1 50.9v5M226.7 40.7v5.1M226.7 50.9v7.6M229.2 50.9v5M231.8 40.7v5.1M231.8 50.9v5M234.3 40.7v5.1M234.3 50.9v5M236.8 40.7v5.1M236.8 50.9v7.6M239.4 40.7v5.1"/>
<path d="M239.4 50.9v5M241.9 50.9v5M244.5 40.7v5.1M244.5 50.9v5M247 50.9v5M249.5 40.7v5.1M249.5 50.9v5M252.1 40.7v5.1M252.1 50.9v5M254.6 40.7v5.1M254.6 50.9v7.6M274.9 58.2h3.8"/>
<path d="M23.5 78.8h3.1M28.2 78.8h3.1M32.8 78.8h3.1M35.6 69.9h1.3M36.2 61v7.6M36.2 69.3v1.2M37.4 78.8h3.1M42 78.8h3.2M46.7 78.8h3.1M51.3 78.8h3.1M55.9 78.8h5.9M59.1 62.9v2.9"/>
<path d="M59.1 67.3v2.8M59.1 71.6v2.9M59.1 76v5.9M63.3 78.8h2.8M67.6 78.8h2.8M69.2 71.2h2.6M71.9 78.8h2.7M76.1 78.8h2.8M80.4 78.8h2.8M84.7 78.8h2.7M88.9 78.8h2.8M93.2 78.8h2.7"/>
<path d="M97.5 78.8h2.7M101.7 78.8h2.8M102.2 66.1h2.6M106 78.8h2.8M109.9 66.1h2.5M110.3 78.8h2.7M114.5 78.8h2.8M118.8 78.8h2.7M123 78.8h2.8M127.3 78.8h2.8M131.6 78.8h2.7M135.8 78.8h2.8"/>
<path d="M140.1 78.8h6.2M142.9 62.9v2.9M142.9 67.3v2.8M142.9 71.6v2.9M142.9 76v2.8M147.8 78.8h3.5M152.8 78.8h3.4M157.7 78.8h3.5M162.7 78.8h3.4M167.6 78.8h3.5M172.6 78.8h3.4M177.5 78.8h16.8"/>
<path d="M181 78.8v3M191.1 62.9v2.9M191.1 67.3v2.8M191.1 71.6v2.9M191.1 76v2.8M195.7 78.8h3.2M200.4 78.8h3.1M205 78.8h3.2M209.7 78.8h3.1M214.3 78.8h3.1M218.9 78.8h3.1M223.5 78.8h6.2"/>
<path d="M226.7 78.8v3M231.2 78.8h3M235.7 78.8h3M240.2 78.8h3.1M244.8 78.8h3M249.3 78.8h3M253.8 78.8h3M258.3 78.8h3.1M262.9 78.8h3M267.4 78.8h3M271.9 78.8h3M36.2 91.5v7.6"/>
<path d="M40.7 90.2h1.2M41.3 89.6v1.2M41.3 91.5v7.6M59.1 83.4v3.2M59.1 88.1v3.1M59.1 92.7v3.1M59.1 97.3v3.1M181 83.2v3M181 87.7v3M181 92.2v3M181 96.6v3M191.1 99.1h2.6"/>
<path d="M203.8 99.1v3.1M208.9 96.6h2.5M226.7 83.2v3M226.7 87.7v3M226.7 92.2v3M226.7 96.6v3M252.1 91.5v7.6M252.1 99.7v1.3M257.2 91.5v7.6M262.2 91.5v7.6M18.4 101h3.8M23.5 114.3h3.1"/>
<path d="M28.2 114.3h3.1M32.8 114.3h3.1M37.4 114.3h3.1M42 114.3h3.2M46.7 114.3h3.1M51.3 114.3h3.1M59.1 101.9v3.2M59.1 106.6v3.1M59.1 111.2v3.1h-3.2M71.1 115.6h1.3M71.8 106.7v7.6M71.8 115v1.2"/>
<path d="M76.9 106.7v5.1M81.9 106.7v5.1M87 106.7v7.6M99.1 115.6h1.2M99.7 106.7v7.6M99.7 115v1.2M104.8 106.7v5.1M109.9 106.7v5.1M114.9 106.7v7.6M137.8 114.3v3.1M137.8 118.9v3.1M145.4 111.8v2.5"/>
<path d="M153 114.3v3.1M153 118.9v3.1M181 101.1v3M181 105.6v3M181 110.1v2.9M181 114.5v3M181 119v5.9M191.1 106.7h2.6M191.1 104.2h2.6M191.1 101.6h2.6M203.8 103.7v3M208.9 109.3h2.5"/>
<path d="M212.1 109.3h1.2M212.7 108.6v1.3M226.7 101.1v3M226.7 105.6v3M226.7 110.1v2.9M226.7 114.5v3M226.7 119v5.9M241.9 111.8v2.5M241.9 119.4v2.6M244.5 109.3h2.5M246.2 106l1.4 1.4M246.2 106h.1"/>
<path d="M246.2 106l.9 .3M246.2 106l.4 .8 .5-.5M246.3 106.1h.2M246.3 106.2h.5M246.4 106.3h.7M246.4 106.4h.6M246.5 106.6h.4M246.5 106.7h.3M246.6 106.8h.1M247.4 105.8l1.4 1.4M247.4 105.8l.9 .4M247.4 105.8l.4 .9"/>
<path d="M247.4 105.9h.1M247.4 106h.3M247.5 106.1h.5M247.5 106.2h.8M247.6 106.3h.6M247.6 106.4h.4M247.7 106.6h.2M247.8 106.7h.1M248.3 106.2l-.5 .5M249.5 109.3h2.6M251.4 100.4h1.3M257.2 104.2v2.5"/>
<path d="M257.2 111.8v2.5M257.2 119.4v2.6M274.9 101h3.8M33.7 132.1h7.6M66.7 137.2h5.1M89.5 129.6h2.6M97.2 129.6h2.5M125.1 139.7h7.6M142.9 124.5h1.5M146.4 124.5h1.6M181 126.4v3M181 130.9v3"/>
<path d="M181 135.4v2.9M181 139.8v3M181 122h3.2M185.7 122h3.2M190.4 122h3.2M195.1 122h3.3M199.9 122h3.2M204.6 122h3.2M209.3 122h3.2M214 122h3.2M218.7 122h3.3M223.5 122h3.2"/>
<path d="M226.7 126.4v3M226.7 130.9v3M226.7 135.4v2.9M226.7 139.8v3M236.8 124.5h2.6M241.9 127v2.6M241.9 134.7v2.5M244.5 139.7h2.5M246.2 136.4l1.4 1.4M246.2 136.4l.9 .4-.5 .5zM246.3 136.5h.1M246.3 136.6h.3"/>
<path d="M246.4 136.7h.5M246.4 136.8h.7M246.5 137h.5M246.5 137.1h.3M246.6 137.2h.1M247.4 136.3l1.4 1.4M247.4 136.3l.9 .4-.5 .5zM247.4 136.4h.1M247.5 136.5h.3M247.5 136.6h.6M247.6 136.7h.6M247.6 136.8h.5"/>
<path d="M247.7 137h.3M247.7 137.1h.2M249.5 139.7h2.6M257.2 127v2.6M257.2 134.7v2.5M18.4 143.9h3.8M31.8 155h1.2M32.4 154.3v1.3M33.7 155h7.6M36.2 149.9h5.1M36.2 147.4h5.1M66.7 149.9h5.1"/>
<path d="M66.7 147.4h5.1M66.7 142.3h5.1M127.6 157.5h5.1M127.6 155h5.1M127.6 152.4h5.1M132.7 159.1l2 .9-2 1M158.1 157.5h5.1M158.1 155h5.1M158.1 152.4h5.1M158.1 149.9h5.1M158.1 147.4h5.1M181 144.3v3"/>
<path d="M181 148.8v2.9M181 153.2v3M181 157.7v3M193.7 152.4h7.6M193.7 147.4h5.1M193.7 142.3h7.6M201.9 152.4h1.3M202.5 151.8v1.3M226.7 144.3v3M226.7 148.8v2.9M226.7 153.2v3M226.7 157.7v3"/>
<path d="M252.1 149.9v7.6M257.2 142.3v2.5M257.2 149.9v7.6M261.6 148.6h1.3M262.2 148v1.2M262.2 149.9v7.6M274.9 143.9h3.8M36.2 160v3.1M36.2 164.6v3.1M36.2 170.2v2.5M71.8 167.7v2.5M71.8 175.3v2.5"/>
<path d="M76.9 162.6h2.5M125.1 172.7h7.6M127.6 167.7h5.1M127.6 165.1h5.1M127.6 162.6h5.1M127.6 160h5.1M158.1 167.7h5.1M158.1 165.1h5.1M158.1 162.6h5.1M158.1 160h5.1M175.4 165.9v2.5M175.4 173.5v2.6"/>
<path d="M175.4 177.4v2.6M181 162.2v2.9M226.7 162.2v2.9M233.7 166.4v20.3M233.7 176.6h41.2M233.7 171.5h41.2M274.9 166.4h-95.2v20.3M64.4 186.7v3.8M97.2 182.9h2.5M104.8 182.9h2.5M106.5 186.7v3.8M148.6 186.7v3.8"/>
<path d="M190.7 186.7v3.8M232.8 186.7v3.8M233.7 181.6h41.2M264.8 181.6v5.1"/>
<circle cx="41.2" cy="32.1" r=".99"/>
<circle cx="41.2" cy="36.2" r=".99"/>
<circle cx="45.2" cy="36.1" r=".99"/>
<circle cx="45.3" cy="32" r=".99"/>
<circle cx="92.1" cy="56.9" r=".99"/>
</g>
<g fill="#c90d0c" stroke="#c90d0c" stroke-width=".21">
<path d="M205.3 35.9a1.4 1.4 0 0 1 2.3 .3 1.4 1.4 0 0 1-.9 2.1 1.4 1.4 0 0 1-1.7-1.4h.2a1.15 1.15 0 0 1 1.6-1.1 1.15 1.15 0 0 1 .3 1.9 1.15 1.15 0 0 1-1.8-.5l-.1-.3h-.2z" fill-rule="evenodd"/>
<path d="M210.7 50.2h.2a.51 .51 0 0 0 .5 .5 .51 .51 0 0 0 .5-.5h.3a.76 .76 0 0 1-.8 .8 .76 .76 0 0 1-.7-.8z" fill-rule="evenodd"/>
<path d="M208.1 50.2h.3a.51 .51 0 0 0 .5 .5 .51 .51 0 0 0 .5-.5h.3a.76 .76 0 0 1-.8 .8 .76 .76 0 0 1-.8-.8z" fill-rule="evenodd"/>
<path d="M205.6 50.2h.2a.51 .51 0 0 0 .6 .5 .51 .51 0 0 0 .5-.5h.2a.76 .76 0 0 1-.7 .8 .76 .76 0 0 1-.8-.8z" fill-rule="evenodd"/>
<path d="M210.9 45.9a.75 .75 0 0 1 .8-.2 .75 .75 0 0 1 .5 .7h-.3a.51 .51 0 0 0-.5-.5 .51 .51 0 0 0-.5 .5h-.2z" fill-rule="evenodd"/>
<path d="M208.4 45.9a.75 .75 0 0 1 .8-.2 .75 .75 0 0 1 .5 .7h-.3a.51 .51 0 0 0-.5-.5 .51 .51 0 0 0-.5 .5h-.3z" fill-rule="evenodd"/>
<path d="M205.8 45.9a.75 .75 0 0 1 .9-.2 .75 .75 0 0 1 .4 .7h-.2a.51 .51 0 0 0-.5-.5 .51 .51 0 0 0-.6 .5h-.2z" fill-rule="evenodd"/>
<path d="M215.8 50.2h.2a.51 .51 0 0 0 .5 .5 .51 .51 0 0 0 .5-.5h.3a.76 .76 0 0 1-.8 .8 .76 .76 0 0 1-.7-.8z" fill-rule="evenodd"/>
<path d="M213.2 50.2h.3a.51 .51 0 0 0 .5 .5 .51 .51 0 0 0 .5-.5h.2a.76 .76 0 0 1-.7 .8 .76 .76 0 0 1-.8-.8z" fill-rule="evenodd"/>
<path d="M216 45.9a.75 .75 0 0 1 .8-.2 .75 .75 0 0 1 .5 .7h-.3a.51 .51 0 0 0-.5-.5 .51 .51 0 0 0-.5 .5h-.2z" fill-rule="evenodd"/>
<path d="M213.4 45.9a.75 .75 0 0 1 .9-.2 .75 .75 0 0 1 .4 .7h-.2a.51 .51 0 0 0-.5-.5 .51 .51 0 0 0-.5 .5h-.3z" fill-rule="evenodd"/>
<path d="M223.4 50.2h.2a.51 .51 0 0 0 .5 .5 .51 .51 0 0 0 .5-.5h.3a.76 .76 0 0 1-.8 .8 .76 .76 0 0 1-.7-.8z" fill-rule="evenodd"/>
<path d="M220.8 50.2h.3a.51 .51 0 0 0 .5 .5 .51 .51 0 0 0 .5-.5h.3a.76 .76 0 0 1-.8 .8 .76 .76 0 0 1-.8-.8z" fill-rule="evenodd"/>
<path d="M218.3 50.2h.2a.51 .51 0 0 0 .6 .5 .51 .51 0 0 0 .5-.5h.2a.76 .76 0 0 1-.7 .8 .76 .76 0 0 1-.8-.8z" fill-rule="evenodd"/>
<path d="M223.6 45.9a.75 .75 0 0 1 .8-.2 .75 .75 0 0 1 .5 .7h-.3a.51 .51 0 0 0-.5-.5 .51 .51 0 0 0-.5 .5h-.2z" fill-rule="evenodd"/>
<path d="M221.1 45.9a.75 .75 0 0 1 .8-.2 .75 .75 0 0 1 .5 .7h-.3a.51 .51 0 0 0-.5-.5 .51 .51 0 0 0-.5 .5h-.3z" fill-rule="evenodd"/>
<path d="M218.5 45.9a.75 .75 0 0 1 .9-.2 .75 .75 0 0 1 .4 .7h-.2a.51 .51 0 0 0-.5-.5 .51 .51 0 0 0-.6 .5h-.2z" fill-rule="evenodd"/>
<path d="M228.5 50.2h.2a.51 .51 0 0 0 .5 .5 .51 .51 0 0 0 .5-.5h.3a.76 .76 0 0 1-.8 .8 .76 .76 0 0 1-.7-.8z" fill-rule="evenodd"/>
<path d="M225.9 50.2h.3a.51 .51 0 0 0 .5 .5 .51 .51 0 0 0 .5-.5h.2a.76 .76 0 0 1-.7 .8 .76 .76 0 0 1-.8-.8z" fill-rule="evenodd"/>
<path d="M228.7 45.9a.76 .76 0 0 1 .8-.2 .76 .76 0 0 1 .5 .7h-.3a.51 .51 0 0 0-.5-.5 .51 .51 0 0 0-.5 .5h-.2z" fill-rule="evenodd"/>
<path d="M226.1 45.9a.75 .75 0 0 1 .9-.2 .75 .75 0 0 1 .4 .7h-.2a.51 .51 0 0 0-.5-.5 .51 .51 0 0 0-.5 .5h-.3z" fill-rule="evenodd"/>
<path d="M236.1 50.2h.2a.51 .51 0 0 0 .5 .5 .51 .51 0 0 0 .5-.5h.3a.76 .76 0 0 1-.8 .8 .76 .76 0 0 1-.7-.8z" fill-rule="evenodd"/>
<path d="M233.5 50.2h.3a.51 .51 0 0 0 .5 .5 .51 .51 0 0 0 .5-.5h.3a.76 .76 0 0 1-.8 .8 .76 .76 0 0 1-.8-.8z" fill-rule="evenodd"/>
<path d="M231 50.2h.2a.51 .51 0 0 0 .6 .5 .51 .51 0 0 0 .5-.5h.2a.76 .76 0 0 1-.7 .8 .76 .76 0 0 1-.8-.8z" fill-rule="evenodd"/>
<path d="M236.3 45.9a.76 .76 0 0 1 .8-.2 .76 .76 0 0 1 .5 .7h-.3a.51 .51 0 0 0-.5-.5 .51 .51 0 0 0-.5 .5h-.2z" fill-rule="evenodd"/>
<path d="M233.7 45.9a.76 .76 0 0 1 .9-.2 .76 .76 0 0 1 .5 .7h-.3a.51 .51 0 0 0-.5-.5 .51 .51 0 0 0-.5 .5h-.3z" fill-rule="evenodd"/>
<path d="M231.2 45.9a.76 .76 0 0 1 .8-.2 .76 .76 0 0 1 .5 .7h-.2a.51 .51 0 0 0-.5-.5 .51 .51 0 0 0-.6 .5h-.2z" fill-rule="evenodd"/>
<path d="M241.2 50.2h.2a.51 .51 0 0 0 .5 .5 .51 .51 0 0 0 .5-.5h.3a.76 .76 0 0 1-.8 .8 .76 .76 0 0 1-.7-.8z" fill-rule="evenodd"/>
<path d="M238.6 50.2h.3a.51 .51 0 0 0 .5 .5 .51 .51 0 0 0 .5-.5h.2a.76 .76 0 0 1-.7 .8 .76 .76 0 0 1-.8-.8z" fill-rule="evenodd"/>
<path d="M241.4 45.9a.76 .76 0 0 1 .8-.2 .76 .76 0 0 1 .5 .7h-.3a.51 .51 0 0 0-.5-.5 .51 .51 0 0 0-.5 .5h-.2z" fill-rule="evenodd"/>
<path d="M238.8 45.9a.76 .76 0 0 1 .9-.2 .76 .76 0 0 1 .4 .7h-.2a.51 .51 0 0 0-.5-.5 .51 .51 0 0 0-.5 .5h-.3z" fill-rule="evenodd"/>
<path d="M246.2 50.2h.3a.51 .51 0 0 0 .5 .5 .51 .51 0 0 0 .5-.5h.3a.76 .76 0 0 1-.8 .8 .76 .76 0 0 1-.8-.8z" fill-rule="evenodd"/>
<path d="M243.7 50.2h.2a.51 .51 0 0 0 .6 .5 .51 .51 0 0 0 .5-.5h.2a.76 .76 0 0 1-.7 .8 .76 .76 0 0 1-.8-.8z" fill-rule="evenodd"/>
<path d="M246.4 45.9a.76 .76 0 0 1 .9-.2 .76 .76 0 0 1 .5 .7h-.3a.51 .51 0 0 0-.5-.5 .51 .51 0 0 0-.5 .5h-.3z" fill-rule="evenodd"/>
<path d="M243.9 45.9a.76 .76 0 0 1 .8-.2 .76 .76 0 0 1 .5 .7h-.2a.51 .51 0 0 0-.5-.5 .51 .51 0 0 0-.6 .5h-.2z" fill-rule="evenodd"/>
<path d="M253.9 50.2h.2a.51 .51 0 0 0 .5 .5 .51 .51 0 0 0 .5-.5h.3a.76 .76 0 0 1-.8 .8 .76 .76 0 0 1-.7-.8z" fill-rule="evenodd"/>
<path d="M251.3 50.2h.3a.51 .51 0 0 0 .5 .5 .51 .51 0 0 0 .5-.5h.2a.76 .76 0 0 1-.7 .8 .76 .76 0 0 1-.8-.8z" fill-rule="evenodd"/>
<path d="M248.8 50.2h.2a.51 .51 0 0 0 .5 .5 .51 .51 0 0 0 .5-.5h.3a.76 .76 0 0 1-.8 .8 .76 .76 0 0 1-.7-.8z" fill-rule="evenodd"/>
<path d="M254.1 45.9a.76 .76 0 0 1 .8-.2 .76 .76 0 0 1 .5 .7h-.3a.51 .51 0 0 0-.5-.5 .51 .51 0 0 0-.5 .5h-.2z" fill-rule="evenodd"/>
<path d="M251.5 45.9a.76 .76 0 0 1 .9-.2 .76 .76 0 0 1 .4 .7h-.2a.51 .51 0 0 0-.5-.5 .51 .51 0 0 0-.5 .5h-.3z" fill-rule="evenodd"/>
<path d="M249 45.9a.76 .76 0 0 1 .8-.2 .76 .76 0 0 1 .5 .7h-.3a.51 .51 0 0 0-.5-.5 .51 .51 0 0 0-.5 .5h-.2z" fill-rule="evenodd"/>
<path d="M35.2 68.9a1.4 1.4 0 0 1 2.2 .3 1.4 1.4 0 0 1-.8 2 1.4 1.4 0 0 1-1.8-1.3h.3a1.14 1.14 0 0 1 1.6-1.1 1.14 1.14 0 0 1 .2 1.9 1.14 1.14 0 0 1-1.8-.5v-.3h-.3z" fill-rule="evenodd"/>
<path d="M158.9 35.4a1.39 1.39 0 0 1 2.2 .3 1.39 1.39 0 0 1-.8 2 1.39 1.39 0 0 1-1.8-1.3h.2a1.14 1.14 0 0 1 1.6-1.1 1.14 1.14 0 0 1 .3 1.9 1.14 1.14 0 0 1-1.8-.5l-.1-.3h-.2z" fill-rule="evenodd"/>
<path d="M169 35.4a1.39 1.39 0 0 1 2.2 .3 1.39 1.39 0 0 1-.8 2 1.39 1.39 0 0 1-1.7-1.3h.2a1.14 1.14 0 0 1 1.7-1 1.14 1.14 0 0 1 .1 2 1.14 1.14 0 0 1-1.8-.7v-.3h-.2z" fill-rule="evenodd"/>
<path d="M67 39.8a1.39 1.39 0 0 1 2.2 .2 1.39 1.39 0 0 1-.9 2 1.39 1.39 0 0 1-1.7-1.3h.2a1.14 1.14 0 0 1 1.7-1 1.14 1.14 0 0 1 .1 2 1.14 1.14 0 0 1-1.8-.7v-.3h-.2z" fill-rule="evenodd"/>
<path d="M133 39.8a1.39 1.39 0 0 1 2.2 .2 1.39 1.39 0 0 1-.9 2 1.39 1.39 0 0 1-1.7-1.3h.2a1.15 1.15 0 0 1 1.6-1.1 1.15 1.15 0 0 1 .3 1.9 1.15 1.15 0 0 1-1.8-.5l-.1-.3h-.2z" fill-rule="evenodd"/>
<path d="M98.7 114.7a1.4 1.4 0 0 1 2.2 .2 1.4 1.4 0 0 1-.8 2.1 1.4 1.4 0 0 1-1.8-1.4h.3a1.15 1.15 0 0 1 1.6-1.1 1.15 1.15 0 0 1 .3 1.9 1.15 1.15 0 0 1-1.9-.5v-.3h-.3z" fill-rule="evenodd"/>
<path d="M70.7 114.7a1.4 1.4 0 0 1 2.3 .2 1.4 1.4 0 0 1-.8 2 1.4 1.4 0 0 1-1.8-1.3h.2a1.14 1.14 0 0 1 1.7-.9 1.14 1.14 0 0 1 .2 1.9 1.14 1.14 0 0 1-1.8-.7l-.1-.3h-.2z" fill-rule="evenodd"/>
<path d="M31.4 154a1.4 1.4 0 0 1 2.2 .2 1.4 1.4 0 0 1-.8 2.1 1.4 1.4 0 0 1-1.8-1.3h.3a1.14 1.14 0 0 1 1.6-1.1 1.14 1.14 0 0 1 .2 1.9 1.14 1.14 0 0 1-1.8-.5v-.3h-.3z" fill-rule="evenodd"/>
<path d="M40.3 89.3a1.39 1.39 0 0 1 2.2 .2 1.39 1.39 0 0 1-.8 2.1 1.39 1.39 0 0 1-1.8-1.4h.3a1.14 1.14 0 0 1 1.6-1 1.14 1.14 0 0 1 .2 1.9 1.14 1.14 0 0 1-1.8-.6v-.3h-.3z" fill-rule="evenodd"/>
<path d="M251.1 99.4a1.39 1.39 0 0 1 2.2 .3 1.39 1.39 0 0 1-.9 2 1.39 1.39 0 0 1-1.7-1.3h.2a1.15 1.15 0 0 1 1.6-1.1 1.15 1.15 0 0 1 .3 1.9 1.15 1.15 0 0 1-1.8-.6l-.1-.2h-.2z" fill-rule="evenodd"/>
<path d="M261.2 147.7a1.4 1.4 0 0 1 2.2 .2 1.4 1.4 0 0 1-.8 2.1 1.4 1.4 0 0 1-1.8-1.4h.3a1.15 1.15 0 0 1 1.6-1 1.15 1.15 0 0 1 .3 1.9 1.15 1.15 0 0 1-1.9-.6v-.3h-.3z" fill-rule="evenodd"/>
<path d="M201.5 151.5a1.4 1.4 0 0 1 2.3 .2 1.4 1.4 0 0 1-.8 2 1.4 1.4 0 0 1-1.8-1.3h.2a1.15 1.15 0 0 1 1.6-1 1.15 1.15 0 0 1 .3 1.9 1.15 1.15 0 0 1-1.9-.6v-.3h-.2z" fill-rule="evenodd"/>
<path d="M211.7 108.3a1.4 1.4 0 0 1 2.2 .2 1.4 1.4 0 0 1-.8 2.1 1.4 1.4 0 0 1-1.8-1.3h.3a1.15 1.15 0 0 1 1.6-1.1 1.15 1.15 0 0 1 .3 1.9 1.15 1.15 0 0 1-1.9-.6v-.2h-.3z" fill-rule="evenodd"/>
<circle cx="43.8" cy="45.8" r=".33"/>
</g>
<g fill="none" stroke="#c90d0c" stroke-width=".25">
<path d="M87 33.1h25.4v22.8h-25.4zM211.4 36.9l1.3 1.3h-2.5zM221.6 36.9l1.3 1.3h-2.6zM229.2 36.9l1.3 1.3h-2.6zM241.9 36.9l1.3 1.3h-2.6zM247 36.9l1.3 1.3h-2.6zM33.7 50.9h5.1v10.1h-5.1zM36.2 50.9v10.1M42.6 47.1h2.5M42.6 42h2.5l-1.3 2.5zM42.6 44.5h2.5M43.8 40.7v1.3"/>
<path d="M43.8 49.6v1.3M43.8 47.1l1.3 2.5h-2.5zM45.1 55.9h2.5l-1.2 1.3zM120 55.9h5.1M122.6 56.9l1 .2 1.5 .7M122.6 57l-1.6 .3-.9 .5M158.6 42.7h2.6l-1.3 2.6zM158.6 45.3h2.6M159 50.4h1.8v5h-1.8zM168.8 45.3h2.5M168.8 42.7h2.5l-1.2 2.6zM169.2 50.4h1.7v5h-1.7z"/>
<path d="M205.1 56.6l1.3 1.9 1.2-1.9M215.2 58.5h2.6l-1.3 1.3zM225.4 56.6l1.3 1.9 1.2-1.9M235.6 58.5h2.5l-1.3 1.3zM253.3 58.5h2.6l-1.3 1.3zM69.2 69.9v2.5l-1.2-1.2zM104.8 65.2h5.1v1.8h-5.1zM158.6 60.5h2.6l-1.3 1.3zM168.8 60.5h2.5l-1.2 1.3zM33.7 99.1h10.1v5.1h-10.1zM36.2 90.2l1.3 1.3h-2.6zM186.1 96.6h5v12.7h-5"/>
<path d="M211.4 95.3l1.3 1.3-1.3 1.2zM249.5 86.4h15.3v5.1h-15.3zM256.3 99.1h1.7v5.1h-1.7zM261 99.1h2.5l-1.3 1.3zM69.2 101.6h20.3v5.1h-20.3zM85.7 114.3h2.6l-1.3 1.3zM97.2 101.6h20.3v5.1h-20.3zM113.7 114.3h2.5l-1.3 1.3zM145.4 110.5l1.3 1.3h-2.6zM241 114.3h1.8v5.1h-1.8zM247 109.3l2.5-1.3v2.5zM247 108v2.5"/>
<path d="M256.3 114.3h1.7v5.1h-1.7zM33.7 130.9v2.5l-1.3-1.3zM92.1 128.7h5.1v1.8h-5.1zM125.1 138.5v2.5l-1.3-1.3zM144.4 122.7v3.6M145 123h.8v3h-.8zM146.4 122.7v3.6M188.6 139.7h5.1v15.3h-5.1zM236.8 123.2v2.6l-1.2-1.3zM241 129.6h1.8v5.1h-1.8zM247 139.7l2.5-1.2v2.5zM247 138.5v2.5"/>
<path d="M256.3 129.6h1.7v5.1h-1.7zM201.3 141l1.2 1.3-1.2 1.3zM249.5 157.5h15.3v5.1h-15.3zM252.1 148.6l1.2 1.3h-2.5zM256.3 144.8h1.7v5.1h-1.7zM34.9 172.7h2.6l-1.3 1.3zM70.9 170.2h1.8v5.1h-1.8zM79.4 161.3l1.3 1.3-1.3 1.3zM127 171.5l-1.9 1.2 1.9 1.3M174.1 178.1l1.3 1.9 1.3-1.9M174.5 168.4h1.8v5.1h-1.8zM99.7 182h5.1v1.8h-5.1z"/>
</g>
<path d="M203.8 44.5h53.4v7.6h-53.4zM41.3 127h25.4v30.5h-25.4zM132.7 134.7h25.4v40.6h-25.4z" fill="none" stroke="#c90d0c" stroke-width=".42"/>
<path d="M18.4 11.5h260.3v179h-260.3z" fill="none" stroke="#c90d0c" stroke-width=".32"/>
<g fill="none" stroke="#0dab76" stroke-width=".21">
<path d="M41.2 34.6l.1 .3M41.2 30.5l.1 15.3h-5.1M45.2 34.6h1.2v18.8M45.3 30.4v4.2M99.7 28h22.9v25.4M224.1 30.5v10.2M226.7 28v12.7M234.3 33.1v7.6M244.5 30.5v10.2M43.8 50.9h2.6M71.8 40.7h10.1M76.9 40.7v12.7"/>
<path d="M117.5 40.7h12.7M206.4 40.7h2.5M229.2 55.9v12.7M231.8 55.9v15.3M234.3 55.9v12.7M76.9 61v10.2M97.2 61v10.2M102.2 61v10.2M107.3 61h5.1v5.1M122.6 61v10.2h-50.8M203.8 96.6v2.5M208.9 96.6h-10.1v2.5h-5.1"/>
<path d="M76.9 111.8v17.8h12.6M81.9 111.8v12.7h17.8v17.8h-27.9M104.8 111.8v10.2h-15.3v15.2h-17.7M109.9 111.8v17.8h-10.2M137.8 114.3h15.2M193.7 106.7h5.1v2.6h10.1M203.8 106.7v2.6M244.5 109.3h-2.6v2.5M252.1 109.3h12.7M257.2 106.7v5.1M137.8 122v2.5M142.9 124.5h-25.4v33h10.1"/>
<path d="M148 124.5h22.8v30.5h-7.6M153 122v2.5M239.4 124.5h17.8M241.9 122v5M241.9 137.2v2.5h2.6M252.1 139.7h12.7M257.2 122v5M257.2 137.2v5.1M36.2 155v5M36.2 149.9h-10.1v33h71.1M71.8 149.9v17.8M71.8 147.4h27.9v5h27.9"/>
<path d="M109.9 155h17.7M163.2 149.9h10.2M163.2 152.4h2.5v30.5h-58.4M163.2 147.4h10.2M198.8 147.4h12.6M36.2 167.7v2.5M71.8 177.8v5.1M71.8 162.6h5.1M163.2 165.1h12.2v.8M163.2 167.7h5.1M175.4 176.1v1.3"/>
</g>
<g fill="#0dab76" stroke="#0dab76" stroke-width=".21">
<circle cx="206.4" cy="40.7" r=".51"/>
<circle cx="122.6" cy="40.7" r=".51"/>
<circle cx="36.2" cy="155" r=".51"/>
<circle cx="203.8" cy="109.3" r=".51"/>
<circle cx="45.2" cy="34.6" r=".51"/>
<circle cx="46.4" cy="50.9" r=".51"/>
<circle cx="76.9" cy="71.2" r=".51"/>
<circle cx="102.2" cy="66.1" r=".51"/>
<circle cx="97.2" cy="71.2" r=".51"/>
<circle cx="102.2" cy="71.2" r=".51"/>
<circle cx="71.8" cy="162.6" r=".51"/>
<circle cx="145.4" cy="114.3" r=".51"/>
<circle cx="203.8" cy="96.6" r=".51"/>
<circle cx="257.2" cy="124.5" r=".51"/>
<circle cx="241.9" cy="124.5" r=".51"/>
<circle cx="76.9" cy="40.7" r=".51"/>
<circle cx="153" cy="124.5" r=".51"/>
<circle cx="71.8" cy="182.9" r=".51"/>
<circle cx="137.8" cy="124.5" r=".51"/>
<circle cx="89.5" cy="129.6" r=".51"/>
<circle cx="99.7" cy="129.6" r=".51"/>
<circle cx="257.2" cy="109.3" r=".51"/>
<circle cx="257.2" cy="139.7" r=".51"/>
<circle cx="41.2" cy="34.6" r=".51"/>
<circle cx="41.3" cy="45.8" r=".51"/>
</g>
<use href="#words"/>
</svg>
